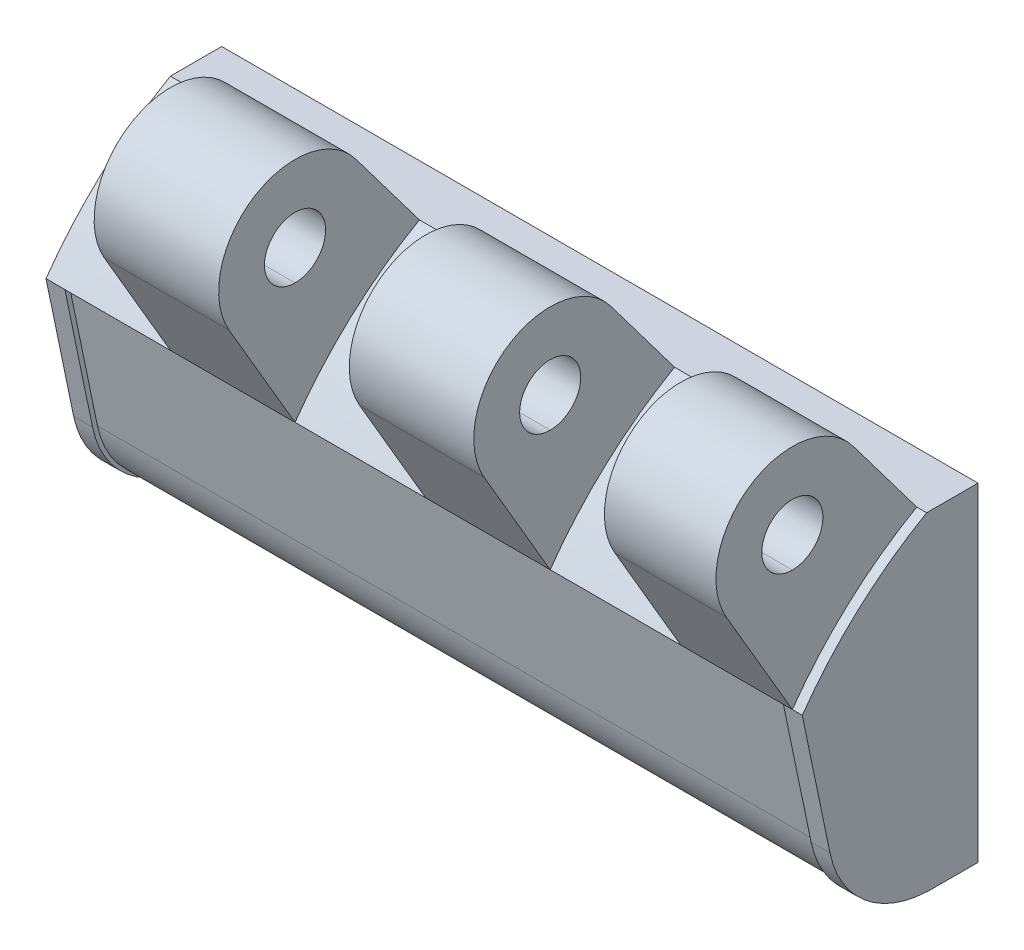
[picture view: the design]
ISO-10303-21;
HEADER;
FILE_DESCRIPTION(('STEP AP214'),'2;1');
FILE_NAME('part.step','',(''),(''),'','','');
FILE_SCHEMA(('AUTOMOTIVE_DESIGN { 1 0 10303 214 1 1 1 1 }'));
ENDSEC;
DATA;
#1=APPLICATION_CONTEXT('core data for automotive mechanical design processes');
#2=APPLICATION_PROTOCOL_DEFINITION('international standard','automotive_design',2000,#1);
#3=PRODUCT_CONTEXT('',#1,'mechanical');
#4=PRODUCT('Part','Part','',(#3));
#5=PRODUCT_RELATED_PRODUCT_CATEGORY('part','',(#4));
#6=PRODUCT_DEFINITION_FORMATION('','',#4);
#7=PRODUCT_DEFINITION_CONTEXT('part definition',#1,'design');
#8=PRODUCT_DEFINITION('design','',#6,#7);
#9=PRODUCT_DEFINITION_SHAPE('','',#8);
#10=(LENGTH_UNIT() NAMED_UNIT(*) SI_UNIT(.MILLI.,.METRE.));
#11=(NAMED_UNIT(*) PLANE_ANGLE_UNIT() SI_UNIT($,.RADIAN.));
#12=(NAMED_UNIT(*) SI_UNIT($,.STERADIAN.) SOLID_ANGLE_UNIT());
#13=UNCERTAINTY_MEASURE_WITH_UNIT(LENGTH_MEASURE(1.E-05),#10,'distance_accuracy_value','');
#14=(GEOMETRIC_REPRESENTATION_CONTEXT(3) GLOBAL_UNCERTAINTY_ASSIGNED_CONTEXT((#13)) GLOBAL_UNIT_ASSIGNED_CONTEXT((#10,
#11,#12)) REPRESENTATION_CONTEXT('',''));
#15=CARTESIAN_POINT('',(0.,0.,0.));
#16=DIRECTION('',(0.,0.,1.));
#17=DIRECTION('',(1.,0.,0.));
#18=AXIS2_PLACEMENT_3D('',#15,#16,#17);
#19=CARTESIAN_POINT('',(38.63875,-2.8772598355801,8.51410225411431));
#20=DIRECTION('',(0.,0.203476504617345,-0.979079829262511));
#21=DIRECTION('',(0.,-0.979079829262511,-0.203476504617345));
#22=AXIS2_PLACEMENT_3D('',#19,#20,#21);
#23=PLANE('',#22);
#24=CARTESIAN_POINT('',(0.,0.,9.11206654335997));
#25=DIRECTION('',(0.,0.203476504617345,-0.979079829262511));
#26=DIRECTION('',(0.,-0.979079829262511,-0.203476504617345));
#27=AXIS2_PLACEMENT_3D('',#24,#25,#26);
#28=ELLIPSE('',#27,5.36217767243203,5.25);
#29=CARTESIAN_POINT('',(0.,5.25,10.2031437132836));
#30=VERTEX_POINT('',#29);
#31=CARTESIAN_POINT('',(4.3913410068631,-2.8772598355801,8.51410225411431));
#32=VERTEX_POINT('',#31);
#33=EDGE_CURVE('E1546',#30,#32,#28,.T.);
#34=ORIENTED_EDGE('',*,*,#33,.T.);
#35=DIRECTION('',(1.,0.,0.));
#36=VECTOR('',#35,1.);
#37=CARTESIAN_POINT('',(38.63875,-2.8772598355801,8.51410225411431));
#38=LINE('',#37,#36);
#39=CARTESIAN_POINT('',(-4.3913410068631,-2.8772598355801,8.51410225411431));
#40=VERTEX_POINT('',#39);
#41=EDGE_CURVE('E398',#32,#40,#38,.F.);
#42=ORIENTED_EDGE('',*,*,#41,.T.);
#43=CARTESIAN_POINT('',(0.,0.,9.11206654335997));
#44=DIRECTION('',(0.,0.203476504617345,-0.979079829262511));
#45=DIRECTION('',(0.,-0.979079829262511,-0.203476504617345));
#46=AXIS2_PLACEMENT_3D('',#43,#44,#45);
#47=ELLIPSE('',#46,5.36217767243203,5.25);
#48=EDGE_CURVE('E607',#40,#30,#47,.T.);
#49=ORIENTED_EDGE('',*,*,#48,.T.);
#50=EDGE_LOOP('',(#34,#42,#49));
#51=FACE_BOUND('',#50,.T.);
#52=ADVANCED_FACE('F14',(#51),#23,.T.);
#53=CARTESIAN_POINT('',(38.63875,-1.75,3.09));
#54=DIRECTION('',(1.,0.,0.));
#55=DIRECTION('',(0.,1.,0.));
#56=AXIS2_PLACEMENT_3D('',#53,#54,#55);
#57=CYLINDRICAL_SURFACE('',#56,5.54);
#58=CARTESIAN_POINT('',(0.,-5.25,7.3843684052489));
#59=CARTESIAN_POINT('',(-0.133828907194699,-5.25003375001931,7.38428145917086));
#60=CARTESIAN_POINT('',(-0.267610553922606,-5.2448846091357,7.38853693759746));
#61=CARTESIAN_POINT('',(-0.533720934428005,-5.22449303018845,7.40506712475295));
#62=CARTESIAN_POINT('',(-0.666051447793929,-5.20926480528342,7.41733054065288));
#63=CARTESIAN_POINT('',(-0.926970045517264,-5.16918804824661,7.44905462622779));
#64=CARTESIAN_POINT('',(-1.05558234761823,-5.1444374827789,7.46844191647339));
#65=CARTESIAN_POINT('',(-1.30960855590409,-5.08570777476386,7.51335022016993));
#66=CARTESIAN_POINT('',(-1.43502144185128,-5.0517257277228,7.53887316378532));
#67=CARTESIAN_POINT('',(-1.68130762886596,-4.97516280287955,7.59468067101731));
#68=CARTESIAN_POINT('',(-1.80220198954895,-4.9326299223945,7.62493845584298));
#69=CARTESIAN_POINT('',(-2.03969557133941,-4.83925951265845,7.68905316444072));
#70=CARTESIAN_POINT('',(-2.15629501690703,-4.78842241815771,7.72290989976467));
#71=CARTESIAN_POINT('',(-2.50013407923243,-4.62348229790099,7.82832401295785));
#72=CARTESIAN_POINT('',(-2.72060185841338,-4.49720570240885,7.90352608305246));
#73=CARTESIAN_POINT('',(-3.05164226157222,-4.27449143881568,8.02225033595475));
#74=CARTESIAN_POINT('',(-3.16919768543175,-4.188081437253,8.0656944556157));
#75=CARTESIAN_POINT('',(-3.39710991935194,-4.00542845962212,8.15110607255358));
#76=CARTESIAN_POINT('',(-3.50746471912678,-3.90918275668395,8.19307315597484));
#77=CARTESIAN_POINT('',(-3.71996372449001,-3.70752770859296,8.27376771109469));
#78=CARTESIAN_POINT('',(-3.82213447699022,-3.6021505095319,8.31250567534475));
#79=CARTESIAN_POINT('',(-4.01794535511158,-3.38234290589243,8.38532231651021));
#80=CARTESIAN_POINT('',(-4.11159227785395,-3.26791985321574,8.41940471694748));
#81=CARTESIAN_POINT('',(-4.23368735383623,-3.10506736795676,8.46191586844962));
#82=CARTESIAN_POINT('',(-4.26616032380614,-3.06030152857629,8.47301775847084));
#83=CARTESIAN_POINT('',(-4.32976362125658,-2.96963143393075,8.4942821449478));
#84=CARTESIAN_POINT('',(-4.36089439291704,-2.92372756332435,8.50444495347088));
#85=CARTESIAN_POINT('',(-4.39134100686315,-2.87725983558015,8.5141022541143));
#86=B_SPLINE_CURVE_WITH_KNOTS('',3,(#58,#59,#60,#61,#62,#63,#64,#65,#66,#67,#68,#69,#70,#71,#72,
#73,#74,#75,#76,#77,#78,#79,#80,#81,#82,#83,#84,#85),.UNSPECIFIED.,.F.,.F.,(4,2,2,2,2,2,2,2,2,2,
2,2,2,4),(0.,0.401244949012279,0.80192527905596,1.19858908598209,1.59537783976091,
1.98999859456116,2.38459869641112,3.1763987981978,3.63270260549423,4.08913326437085,
4.54401777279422,4.99853630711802,5.16772855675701,5.33686437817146),.UNSPECIFIED.);
#87=CARTESIAN_POINT('',(0.,-5.25,7.3843684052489));
#88=VERTEX_POINT('',#87);
#89=EDGE_CURVE('E600',#88,#40,#86,.T.);
#90=ORIENTED_EDGE('',*,*,#89,.T.);
#91=ORIENTED_EDGE('',*,*,#41,.F.);
#92=CARTESIAN_POINT('',(4.3913410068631,-2.8772598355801,8.51410225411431));
#93=CARTESIAN_POINT('',(4.30901059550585,-3.00292273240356,8.48799614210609));
#94=CARTESIAN_POINT('',(4.22168764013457,-3.12442415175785,8.45818131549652));
#95=CARTESIAN_POINT('',(4.03796771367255,-3.35848364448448,8.39274465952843));
#96=CARTESIAN_POINT('',(3.94158066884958,-3.47105125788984,8.3571291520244));
#97=CARTESIAN_POINT('',(3.7401855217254,-3.68719352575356,8.28153449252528));
#98=CARTESIAN_POINT('',(3.63515445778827,-3.79074261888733,8.24154361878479));
#99=CARTESIAN_POINT('',(3.41738224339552,-3.98818571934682,8.15888554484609));
#100=CARTESIAN_POINT('',(3.30463881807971,-4.08207685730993,8.11621755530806));
#101=CARTESIAN_POINT('',(2.95635398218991,-4.34828784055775,7.98685733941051));
#102=CARTESIAN_POINT('',(2.70992059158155,-4.5060387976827,7.89847178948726));
#103=CARTESIAN_POINT('',(2.32219866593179,-4.71075307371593,7.77315807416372));
#104=CARTESIAN_POINT('',(2.19014120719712,-4.7736074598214,7.73264865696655));
#105=CARTESIAN_POINT('',(1.92014141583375,-4.8884615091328,7.65578801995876));
#106=CARTESIAN_POINT('',(1.78219922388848,-4.94046143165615,7.61943670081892));
#107=CARTESIAN_POINT('',(1.51214189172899,-5.02936562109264,7.55543720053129));
#108=CARTESIAN_POINT('',(1.38042076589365,-5.06713507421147,7.52732956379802));
#109=CARTESIAN_POINT('',(1.11328601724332,-5.13244464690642,7.47775012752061));
#110=CARTESIAN_POINT('',(0.977874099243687,-5.15998940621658,7.45627531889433));
#111=CARTESIAN_POINT('',(0.702935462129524,-5.20460806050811,7.42106346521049));
#112=CARTESIAN_POINT('',(0.563381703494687,-5.22157877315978,7.40740277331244));
#113=CARTESIAN_POINT('',(0.352852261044,-5.23860422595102,7.39363653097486));
#114=CARTESIAN_POINT('',(0.282404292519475,-5.242874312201,7.3901684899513));
#115=CARTESIAN_POINT('',(0.141308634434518,-5.24857303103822,7.38553183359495));
#116=CARTESIAN_POINT('',(0.0706609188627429,-5.25000127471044,7.38436353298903));
#117=CARTESIAN_POINT('',(0.,-5.25,7.38436840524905));
#118=B_SPLINE_CURVE_WITH_KNOTS('',3,(#92,#93,#94,#95,#96,#97,#98,#99,#100,#101,#102,#103,#104,
#105,#106,#107,#108,#109,#110,#111,#112,#113,#114,#115,#116,#117),.UNSPECIFIED.,.F.,.F.,(4,2,2,
2,2,2,2,2,2,2,2,2,4),(0.,0.457120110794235,0.913745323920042,1.37162527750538,1.82964087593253,
2.74190293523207,3.1967769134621,3.65164002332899,4.07075607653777,4.48968171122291,
4.91263373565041,5.12453779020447,5.33647084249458),.UNSPECIFIED.);
#119=EDGE_CURVE('E576',#32,#88,#118,.T.);
#120=ORIENTED_EDGE('',*,*,#119,.T.);
#121=EDGE_LOOP('',(#90,#91,#120));
#122=FACE_BOUND('',#121,.T.);
#123=ADVANCED_FACE('F609',(#122),#57,.F.);
#124=CARTESIAN_POINT('',(38.63875,-2.8772598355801,8.51410225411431));
#125=DIRECTION('',(0.,0.203476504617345,-0.979079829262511));
#126=DIRECTION('',(0.,-0.979079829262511,-0.203476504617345));
#127=AXIS2_PLACEMENT_3D('',#124,#125,#126);
#128=PLANE('',#127);
#129=CARTESIAN_POINT('',(30.5,0.,9.11206654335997));
#130=DIRECTION('',(0.,0.203476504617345,-0.979079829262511));
#131=DIRECTION('',(0.,-0.979079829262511,-0.203476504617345));
#132=AXIS2_PLACEMENT_3D('',#129,#130,#131);
#133=ELLIPSE('',#132,5.36217767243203,5.25);
#134=CARTESIAN_POINT('',(30.5,5.25,10.2031437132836));
#135=VERTEX_POINT('',#134);
#136=CARTESIAN_POINT('',(34.8913410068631,-2.8772598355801,8.51410225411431));
#137=VERTEX_POINT('',#136);
#138=EDGE_CURVE('E551',#135,#137,#133,.T.);
#139=ORIENTED_EDGE('',*,*,#138,.T.);
#140=DIRECTION('',(1.,0.,0.));
#141=VECTOR('',#140,1.);
#142=CARTESIAN_POINT('',(38.63875,-2.8772598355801,8.51410225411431));
#143=LINE('',#142,#141);
#144=CARTESIAN_POINT('',(26.1086589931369,-2.8772598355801,8.51410225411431));
#145=VERTEX_POINT('',#144);
#146=EDGE_CURVE('E396',#137,#145,#143,.F.);
#147=ORIENTED_EDGE('',*,*,#146,.T.);
#148=CARTESIAN_POINT('',(30.5,0.,9.11206654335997));
#149=DIRECTION('',(0.,0.203476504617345,-0.979079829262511));
#150=DIRECTION('',(0.,-0.979079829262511,-0.203476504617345));
#151=AXIS2_PLACEMENT_3D('',#148,#149,#150);
#152=ELLIPSE('',#151,5.36217767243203,5.25);
#153=EDGE_CURVE('E574',#145,#135,#152,.T.);
#154=ORIENTED_EDGE('',*,*,#153,.T.);
#155=EDGE_LOOP('',(#139,#147,#154));
#156=FACE_BOUND('',#155,.T.);
#157=ADVANCED_FACE('F562',(#156),#128,.T.);
#158=CARTESIAN_POINT('',(38.63875,-1.75,3.09));
#159=DIRECTION('',(1.,0.,0.));
#160=DIRECTION('',(0.,1.,0.));
#161=AXIS2_PLACEMENT_3D('',#158,#159,#160);
#162=CYLINDRICAL_SURFACE('',#161,5.54);
#163=CARTESIAN_POINT('',(30.5,-5.25,7.3843684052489));
#164=CARTESIAN_POINT('',(30.3661710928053,-5.25003375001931,7.38428145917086));
#165=CARTESIAN_POINT('',(30.2323894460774,-5.2448846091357,7.38853693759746));
#166=CARTESIAN_POINT('',(29.966279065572,-5.22449303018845,7.40506712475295));
#167=CARTESIAN_POINT('',(29.8339485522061,-5.20926480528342,7.41733054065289));
#168=CARTESIAN_POINT('',(29.5730299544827,-5.16918804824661,7.44905462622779));
#169=CARTESIAN_POINT('',(29.4444176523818,-5.1444374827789,7.46844191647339));
#170=CARTESIAN_POINT('',(29.1903914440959,-5.08570777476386,7.51335022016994));
#171=CARTESIAN_POINT('',(29.0649785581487,-5.0517257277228,7.53887316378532));
#172=CARTESIAN_POINT('',(28.818692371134,-4.97516280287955,7.59468067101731));
#173=CARTESIAN_POINT('',(28.697798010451,-4.93262992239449,7.62493845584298));
#174=CARTESIAN_POINT('',(28.4603044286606,-4.83925951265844,7.68905316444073));
#175=CARTESIAN_POINT('',(28.343704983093,-4.7884224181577,7.72290989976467));
#176=CARTESIAN_POINT('',(27.9998659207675,-4.62348229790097,7.82832401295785));
#177=CARTESIAN_POINT('',(27.7793981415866,-4.49720570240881,7.90352608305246));
#178=CARTESIAN_POINT('',(27.4483577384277,-4.27449143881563,8.02225033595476));
#179=CARTESIAN_POINT('',(27.3308023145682,-4.18808143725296,8.06569445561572));
#180=CARTESIAN_POINT('',(27.102890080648,-4.00542845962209,8.1511060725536));
#181=CARTESIAN_POINT('',(26.9925352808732,-3.90918275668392,8.19307315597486));
#182=CARTESIAN_POINT('',(26.78003627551,-3.70752770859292,8.27376771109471));
#183=CARTESIAN_POINT('',(26.6778655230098,-3.60215050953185,8.31250567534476));
#184=CARTESIAN_POINT('',(26.4820546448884,-3.38234290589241,8.38532231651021));
#185=CARTESIAN_POINT('',(26.388407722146,-3.26791985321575,8.41940471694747));
#186=CARTESIAN_POINT('',(26.2663126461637,-3.10506736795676,8.46191586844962));
#187=CARTESIAN_POINT('',(26.2338396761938,-3.06030152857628,8.47301775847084));
#188=CARTESIAN_POINT('',(26.1702363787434,-2.96963143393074,8.4942821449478));
#189=CARTESIAN_POINT('',(26.139105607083,-2.92372756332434,8.50444495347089));
#190=CARTESIAN_POINT('',(26.1086589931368,-2.87725983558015,8.5141022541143));
#191=B_SPLINE_CURVE_WITH_KNOTS('',3,(#163,#164,#165,#166,#167,#168,#169,#170,#171,#172,#173,
#174,#175,#176,#177,#178,#179,#180,#181,#182,#183,#184,#185,#186,#187,#188,#189,#190),
.UNSPECIFIED.,.F.,.F.,(4,2,2,2,2,2,2,2,2,2,2,2,2,4),(0.,0.401244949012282,0.801925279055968,
1.1985890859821,1.59537783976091,1.98999859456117,2.38459869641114,3.17639879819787,
3.63270260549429,4.0891332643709,4.54401777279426,4.99853630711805,5.16772855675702,
5.33686437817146),.UNSPECIFIED.);
#192=CARTESIAN_POINT('',(30.5,-5.25,7.3843684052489));
#193=VERTEX_POINT('',#192);
#194=EDGE_CURVE('E567',#193,#145,#191,.T.);
#195=ORIENTED_EDGE('',*,*,#194,.T.);
#196=ORIENTED_EDGE('',*,*,#146,.F.);
#197=CARTESIAN_POINT('',(34.8913410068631,-2.8772598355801,8.51410225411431));
#198=CARTESIAN_POINT('',(34.8090105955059,-3.00292273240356,8.48799614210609));
#199=CARTESIAN_POINT('',(34.7216876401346,-3.12442415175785,8.45818131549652));
#200=CARTESIAN_POINT('',(34.5379677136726,-3.35848364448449,8.39274465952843));
#201=CARTESIAN_POINT('',(34.4415806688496,-3.47105125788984,8.3571291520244));
#202=CARTESIAN_POINT('',(34.2401855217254,-3.68719352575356,8.28153449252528));
#203=CARTESIAN_POINT('',(34.1351544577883,-3.79074261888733,8.24154361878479));
#204=CARTESIAN_POINT('',(33.9173822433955,-3.98818571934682,8.15888554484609));
#205=CARTESIAN_POINT('',(33.8046388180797,-4.08207685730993,8.11621755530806));
#206=CARTESIAN_POINT('',(33.4563539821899,-4.34828784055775,7.98685733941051));
#207=CARTESIAN_POINT('',(33.2099205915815,-4.5060387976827,7.89847178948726));
#208=CARTESIAN_POINT('',(32.8221986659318,-4.71075307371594,7.77315807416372));
#209=CARTESIAN_POINT('',(32.6901412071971,-4.7736074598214,7.73264865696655));
#210=CARTESIAN_POINT('',(32.4201414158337,-4.8884615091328,7.65578801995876));
#211=CARTESIAN_POINT('',(32.2821992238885,-4.94046143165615,7.61943670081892));
#212=CARTESIAN_POINT('',(32.012141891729,-5.02936562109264,7.55543720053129));
#213=CARTESIAN_POINT('',(31.8804207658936,-5.06713507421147,7.52732956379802));
#214=CARTESIAN_POINT('',(31.6132860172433,-5.13244464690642,7.47775012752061));
#215=CARTESIAN_POINT('',(31.4778740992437,-5.15998940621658,7.45627531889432));
#216=CARTESIAN_POINT('',(31.2029354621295,-5.20460806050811,7.42106346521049));
#217=CARTESIAN_POINT('',(31.0633817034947,-5.22157877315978,7.40740277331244));
#218=CARTESIAN_POINT('',(30.852852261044,-5.23860422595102,7.39363653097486));
#219=CARTESIAN_POINT('',(30.7824042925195,-5.242874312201,7.3901684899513));
#220=CARTESIAN_POINT('',(30.6413086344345,-5.24857303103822,7.38553183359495));
#221=CARTESIAN_POINT('',(30.5706609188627,-5.25000127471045,7.38436353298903));
#222=CARTESIAN_POINT('',(30.5,-5.25,7.38436840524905));
#223=B_SPLINE_CURVE_WITH_KNOTS('',3,(#197,#198,#199,#200,#201,#202,#203,#204,#205,#206,#207,
#208,#209,#210,#211,#212,#213,#214,#215,#216,#217,#218,#219,#220,#221,#222),.UNSPECIFIED.,.F.,
.F.,(4,2,2,2,2,2,2,2,2,2,2,2,4),(0.,0.457120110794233,0.913745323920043,1.37162527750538,
1.82964087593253,2.74190293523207,3.1967769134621,3.65164002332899,4.07075607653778,
4.48968171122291,4.91263373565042,5.12453779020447,5.33647084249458),.UNSPECIFIED.);
#224=EDGE_CURVE('E542',#137,#193,#223,.T.);
#225=ORIENTED_EDGE('',*,*,#224,.T.);
#226=EDGE_LOOP('',(#195,#196,#225));
#227=FACE_BOUND('',#226,.T.);
#228=ADVANCED_FACE('F557',(#227),#162,.F.);
#229=CARTESIAN_POINT('',(38.7625,-1.75,3.09));
#230=DIRECTION('',(1.,0.,0.));
#231=DIRECTION('',(0.,1.,0.));
#232=AXIS2_PLACEMENT_3D('',#229,#230,#231);
#233=CYLINDRICAL_SURFACE('',#232,5.54);
#234=CARTESIAN_POINT('',(-8.2625,-1.75,3.09));
#235=DIRECTION('',(1.,0.,0.));
#236=DIRECTION('',(0.,1.,0.));
#237=AXIS2_PLACEMENT_3D('',#234,#235,#236);
#238=CIRCLE('',#237,5.54);
#239=CARTESIAN_POINT('',(-8.2625,-7.2834549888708,3.35921345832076));
#240=VERTEX_POINT('',#239);
#241=CARTESIAN_POINT('',(-8.2625,-2.8772598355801,8.51410225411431));
#242=VERTEX_POINT('',#241);
#243=EDGE_CURVE('E539',#240,#242,#238,.F.);
#244=ORIENTED_EDGE('',*,*,#243,.F.);
#245=DIRECTION('',(1.,0.,0.));
#246=VECTOR('',#245,1.);
#247=CARTESIAN_POINT('',(38.7625,-7.2834549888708,3.35921345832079));
#248=LINE('',#247,#246);
#249=CARTESIAN_POINT('',(-8.13875,-7.2834549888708,3.35921345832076));
#250=VERTEX_POINT('',#249);
#251=EDGE_CURVE('E327',#240,#250,#248,.T.);
#252=ORIENTED_EDGE('',*,*,#251,.T.);
#253=CARTESIAN_POINT('',(-8.13875,-1.75,3.09));
#254=DIRECTION('',(1.,0.,0.));
#255=DIRECTION('',(0.,1.,0.));
#256=AXIS2_PLACEMENT_3D('',#253,#254,#255);
#257=CIRCLE('',#256,5.54);
#258=CARTESIAN_POINT('',(-8.13875,-2.8772598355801,8.51410225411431));
#259=VERTEX_POINT('',#258);
#260=EDGE_CURVE('E17',#250,#259,#257,.F.);
#261=ORIENTED_EDGE('',*,*,#260,.T.);
#262=DIRECTION('',(-1.,0.,0.));
#263=VECTOR('',#262,1.);
#264=CARTESIAN_POINT('',(38.7625,-2.8772598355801,8.51410225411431));
#265=LINE('',#264,#263);
#266=EDGE_CURVE('E315',#259,#242,#265,.T.);
#267=ORIENTED_EDGE('',*,*,#266,.T.);
#268=EDGE_LOOP('',(#244,#252,#261,#267));
#269=FACE_BOUND('',#268,.T.);
#270=ADVANCED_FACE('F330',(#269),#233,.T.);
#271=CARTESIAN_POINT('',(38.7625,-2.8772598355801,8.51410225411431));
#272=DIRECTION('',(0.,0.203476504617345,-0.979079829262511));
#273=DIRECTION('',(0.,-0.979079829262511,-0.203476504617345));
#274=AXIS2_PLACEMENT_3D('',#271,#272,#273);
#275=PLANE('',#274);
#276=DIRECTION('',(-1.,0.,0.));
#277=VECTOR('',#276,1.);
#278=CARTESIAN_POINT('',(38.7625,5.5926726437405,10.2743593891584));
#279=LINE('',#278,#277);
#280=CARTESIAN_POINT('',(-8.2625,5.5926726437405,10.2743593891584));
#281=VERTEX_POINT('',#280);
#282=CARTESIAN_POINT('',(-8.13875,5.5926726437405,10.2743593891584));
#283=VERTEX_POINT('',#282);
#284=EDGE_CURVE('E326',#281,#283,#279,.F.);
#285=ORIENTED_EDGE('',*,*,#284,.F.);
#286=DIRECTION('',(0.,0.979079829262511,0.203476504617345));
#287=VECTOR('',#286,1.);
#288=CARTESIAN_POINT('',(-8.2625,-2.8772598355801,8.51410225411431));
#289=LINE('',#288,#287);
#290=EDGE_CURVE('E322',#242,#281,#289,.T.);
#291=ORIENTED_EDGE('',*,*,#290,.F.);
#292=ORIENTED_EDGE('',*,*,#266,.F.);
#293=DIRECTION('',(0.,0.979079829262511,0.203476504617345));
#294=VECTOR('',#293,1.);
#295=CARTESIAN_POINT('',(-8.13875,-2.8772598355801,8.51410225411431));
#296=LINE('',#295,#294);
#297=EDGE_CURVE('E319',#259,#283,#296,.T.);
#298=ORIENTED_EDGE('',*,*,#297,.T.);
#299=EDGE_LOOP('',(#285,#291,#292,#298));
#300=FACE_BOUND('',#299,.T.);
#301=ADVANCED_FACE('F317',(#300),#275,.F.);
#302=CARTESIAN_POINT('',(6.8,15.5,11.5));
#303=DIRECTION('',(1.,0.,0.));
#304=DIRECTION('',(0.,1.,0.));
#305=AXIS2_PLACEMENT_3D('',#302,#303,#304);
#306=CYLINDRICAL_SURFACE('',#305,2.);
#307=CARTESIAN_POINT('',(6.8,15.5,11.5));
#308=DIRECTION('',(1.,0.,0.));
#309=DIRECTION('',(0.,1.,0.));
#310=AXIS2_PLACEMENT_3D('',#307,#308,#309);
#311=CIRCLE('',#310,2.);
#312=CARTESIAN_POINT('',(6.8,13.5,11.5));
#313=VERTEX_POINT('',#312);
#314=CARTESIAN_POINT('',(6.8,17.5,11.5));
#315=VERTEX_POINT('',#314);
#316=EDGE_CURVE('E525',#313,#315,#311,.F.);
#317=ORIENTED_EDGE('',*,*,#316,.F.);
#318=DIRECTION('',(1.,0.,0.));
#319=VECTOR('',#318,1.);
#320=CARTESIAN_POINT('',(6.8,13.5,11.5));
#321=LINE('',#320,#319);
#322=CARTESIAN_POINT('',(-1.35,13.5,11.5));
#323=VERTEX_POINT('',#322);
#324=EDGE_CURVE('E386',#313,#323,#321,.F.);
#325=ORIENTED_EDGE('',*,*,#324,.T.);
#326=CARTESIAN_POINT('',(-1.35,15.5,11.5));
#327=DIRECTION('',(1.,0.,0.));
#328=DIRECTION('',(0.,1.,0.));
#329=AXIS2_PLACEMENT_3D('',#326,#327,#328);
#330=CIRCLE('',#329,2.);
#331=CARTESIAN_POINT('',(-1.35,17.5,11.5));
#332=VERTEX_POINT('',#331);
#333=EDGE_CURVE('E537',#323,#332,#330,.F.);
#334=ORIENTED_EDGE('',*,*,#333,.T.);
#335=DIRECTION('',(1.,0.,0.));
#336=VECTOR('',#335,1.);
#337=CARTESIAN_POINT('',(6.8,17.5,11.5));
#338=LINE('',#337,#336);
#339=EDGE_CURVE('E384',#332,#315,#338,.T.);
#340=ORIENTED_EDGE('',*,*,#339,.T.);
#341=EDGE_LOOP('',(#317,#325,#334,#340));
#342=FACE_BOUND('',#341,.T.);
#343=ADVANCED_FACE('F1104',(#342),#306,.F.);
#344=CARTESIAN_POINT('',(6.8,15.5,11.5));
#345=DIRECTION('',(1.,0.,0.));
#346=DIRECTION('',(0.,1.,0.));
#347=AXIS2_PLACEMENT_3D('',#344,#345,#346);
#348=CYLINDRICAL_SURFACE('',#347,2.);
#349=CARTESIAN_POINT('',(-1.35,15.5,11.5));
#350=DIRECTION('',(1.,0.,0.));
#351=DIRECTION('',(0.,1.,0.));
#352=AXIS2_PLACEMENT_3D('',#349,#350,#351);
#353=CIRCLE('',#352,2.);
#354=EDGE_CURVE('E534',#332,#323,#353,.F.);
#355=ORIENTED_EDGE('',*,*,#354,.T.);
#356=ORIENTED_EDGE('',*,*,#324,.F.);
#357=CARTESIAN_POINT('',(6.8,15.5,11.5));
#358=DIRECTION('',(1.,0.,0.));
#359=DIRECTION('',(0.,1.,0.));
#360=AXIS2_PLACEMENT_3D('',#357,#358,#359);
#361=CIRCLE('',#360,2.);
#362=EDGE_CURVE('E522',#315,#313,#361,.F.);
#363=ORIENTED_EDGE('',*,*,#362,.F.);
#364=ORIENTED_EDGE('',*,*,#339,.F.);
#365=EDGE_LOOP('',(#355,#356,#363,#364));
#366=FACE_BOUND('',#365,.T.);
#367=ADVANCED_FACE('F1108',(#366),#348,.F.);
#368=CARTESIAN_POINT('',(15.35,15.5,11.5));
#369=DIRECTION('',(-1.,0.,0.));
#370=DIRECTION('',(0.,-1.,0.));
#371=AXIS2_PLACEMENT_3D('',#368,#369,#370);
#372=CYLINDRICAL_SURFACE('',#371,2.);
#373=CARTESIAN_POINT('',(23.5,15.5,11.5));
#374=DIRECTION('',(-1.,0.,0.));
#375=DIRECTION('',(0.,-1.,0.));
#376=AXIS2_PLACEMENT_3D('',#373,#374,#375);
#377=CIRCLE('',#376,2.);
#378=CARTESIAN_POINT('',(23.5,13.5,11.5));
#379=VERTEX_POINT('',#378);
#380=CARTESIAN_POINT('',(23.5,17.5,11.5));
#381=VERTEX_POINT('',#380);
#382=EDGE_CURVE('E379',#379,#381,#377,.T.);
#383=ORIENTED_EDGE('',*,*,#382,.F.);
#384=DIRECTION('',(-1.,0.,0.));
#385=VECTOR('',#384,1.);
#386=CARTESIAN_POINT('',(15.35,13.5,11.5));
#387=LINE('',#386,#385);
#388=CARTESIAN_POINT('',(15.35,13.5,11.5));
#389=VERTEX_POINT('',#388);
#390=EDGE_CURVE('E382',#379,#389,#387,.T.);
#391=ORIENTED_EDGE('',*,*,#390,.T.);
#392=CARTESIAN_POINT('',(15.35,15.5,11.5));
#393=DIRECTION('',(-1.,0.,0.));
#394=DIRECTION('',(0.,-1.,0.));
#395=AXIS2_PLACEMENT_3D('',#392,#393,#394);
#396=CIRCLE('',#395,2.);
#397=CARTESIAN_POINT('',(15.35,17.5,11.5));
#398=VERTEX_POINT('',#397);
#399=EDGE_CURVE('E515',#389,#398,#396,.T.);
#400=ORIENTED_EDGE('',*,*,#399,.T.);
#401=DIRECTION('',(-1.,0.,0.));
#402=VECTOR('',#401,1.);
#403=CARTESIAN_POINT('',(15.35,17.5,11.5));
#404=LINE('',#403,#402);
#405=EDGE_CURVE('E372',#398,#381,#404,.F.);
#406=ORIENTED_EDGE('',*,*,#405,.T.);
#407=EDGE_LOOP('',(#383,#391,#400,#406));
#408=FACE_BOUND('',#407,.T.);
#409=ADVANCED_FACE('F1110',(#408),#372,.F.);
#410=CARTESIAN_POINT('',(15.35,15.5,11.5));
#411=DIRECTION('',(-1.,0.,0.));
#412=DIRECTION('',(0.,-1.,0.));
#413=AXIS2_PLACEMENT_3D('',#410,#411,#412);
#414=CYLINDRICAL_SURFACE('',#413,2.);
#415=CARTESIAN_POINT('',(15.35,15.5,11.5));
#416=DIRECTION('',(-1.,0.,0.));
#417=DIRECTION('',(0.,-1.,0.));
#418=AXIS2_PLACEMENT_3D('',#415,#416,#417);
#419=CIRCLE('',#418,2.);
#420=EDGE_CURVE('E518',#398,#389,#419,.T.);
#421=ORIENTED_EDGE('',*,*,#420,.T.);
#422=ORIENTED_EDGE('',*,*,#390,.F.);
#423=CARTESIAN_POINT('',(23.5,15.5,11.5));
#424=DIRECTION('',(-1.,0.,0.));
#425=DIRECTION('',(0.,-1.,0.));
#426=AXIS2_PLACEMENT_3D('',#423,#424,#425);
#427=CIRCLE('',#426,2.);
#428=EDGE_CURVE('E508',#381,#379,#427,.T.);
#429=ORIENTED_EDGE('',*,*,#428,.F.);
#430=ORIENTED_EDGE('',*,*,#405,.F.);
#431=EDGE_LOOP('',(#421,#422,#429,#430));
#432=FACE_BOUND('',#431,.T.);
#433=ADVANCED_FACE('F1117',(#432),#414,.F.);
#434=CARTESIAN_POINT('',(6.8,12.9766151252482,15.8165412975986));
#435=DIRECTION('',(0.,-0.504676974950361,0.863308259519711));
#436=DIRECTION('',(0.,0.863308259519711,0.504676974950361));
#437=AXIS2_PLACEMENT_3D('',#434,#435,#436);
#438=PLANE('',#437);
#439=DIRECTION('',(0.,-0.863308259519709,-0.504676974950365));
#440=VECTOR('',#439,1.);
#441=CARTESIAN_POINT('',(6.8,12.9766151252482,15.8165412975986));
#442=LINE('',#441,#440);
#443=CARTESIAN_POINT('',(6.8,12.9766151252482,15.8165412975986));
#444=VERTEX_POINT('',#443);
#445=CARTESIAN_POINT('',(6.8,5.59267264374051,11.5));
#446=VERTEX_POINT('',#445);
#447=EDGE_CURVE('E528',#444,#446,#442,.T.);
#448=ORIENTED_EDGE('',*,*,#447,.F.);
#449=DIRECTION('',(1.,0.,0.));
#450=VECTOR('',#449,1.);
#451=CARTESIAN_POINT('',(6.8,12.9766151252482,15.8165412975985));
#452=LINE('',#451,#450);
#453=CARTESIAN_POINT('',(-1.35,12.9766151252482,15.8165412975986));
#454=VERTEX_POINT('',#453);
#455=EDGE_CURVE('E388',#454,#444,#452,.T.);
#456=ORIENTED_EDGE('',*,*,#455,.F.);
#457=DIRECTION('',(0.,-0.863308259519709,-0.504676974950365));
#458=VECTOR('',#457,1.);
#459=CARTESIAN_POINT('',(-1.35,12.9766151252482,15.8165412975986));
#460=LINE('',#459,#458);
#461=CARTESIAN_POINT('',(-1.35,5.59267264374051,11.5));
#462=VERTEX_POINT('',#461);
#463=EDGE_CURVE('E533',#454,#462,#460,.T.);
#464=ORIENTED_EDGE('',*,*,#463,.T.);
#465=DIRECTION('',(-1.,0.,0.));
#466=VECTOR('',#465,1.);
#467=CARTESIAN_POINT('',(38.7625,5.5926726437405,11.5));
#468=LINE('',#467,#466);
#469=EDGE_CURVE('E792',#462,#446,#468,.F.);
#470=ORIENTED_EDGE('',*,*,#469,.T.);
#471=EDGE_LOOP('',(#448,#456,#464,#470));
#472=FACE_BOUND('',#471,.T.);
#473=ADVANCED_FACE('F1092',(#472),#438,.T.);
#474=CARTESIAN_POINT('',(15.35,5.5926726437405,11.5));
#475=DIRECTION('',(0.,-0.504676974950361,0.863308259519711));
#476=DIRECTION('',(0.,0.863308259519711,0.504676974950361));
#477=AXIS2_PLACEMENT_3D('',#474,#475,#476);
#478=PLANE('',#477);
#479=DIRECTION('',(0.,-0.863308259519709,-0.504676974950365));
#480=VECTOR('',#479,1.);
#481=CARTESIAN_POINT('',(15.35,12.9766151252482,15.8165412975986));
#482=LINE('',#481,#480);
#483=CARTESIAN_POINT('',(15.35,12.9766151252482,15.8165412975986));
#484=VERTEX_POINT('',#483);
#485=CARTESIAN_POINT('',(15.35,5.59267264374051,11.5));
#486=VERTEX_POINT('',#485);
#487=EDGE_CURVE('E521',#484,#486,#482,.T.);
#488=ORIENTED_EDGE('',*,*,#487,.T.);
#489=DIRECTION('',(-1.,0.,0.));
#490=VECTOR('',#489,1.);
#491=CARTESIAN_POINT('',(38.7625,5.5926726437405,11.5));
#492=LINE('',#491,#490);
#493=CARTESIAN_POINT('',(23.5,5.59267264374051,11.5));
#494=VERTEX_POINT('',#493);
#495=EDGE_CURVE('E794',#486,#494,#492,.F.);
#496=ORIENTED_EDGE('',*,*,#495,.T.);
#497=DIRECTION('',(0.,-0.863308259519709,-0.504676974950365));
#498=VECTOR('',#497,1.);
#499=CARTESIAN_POINT('',(23.5,12.9766151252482,15.8165412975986));
#500=LINE('',#499,#498);
#501=CARTESIAN_POINT('',(23.5,12.9766151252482,15.8165412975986));
#502=VERTEX_POINT('',#501);
#503=EDGE_CURVE('E507',#502,#494,#500,.T.);
#504=ORIENTED_EDGE('',*,*,#503,.F.);
#505=DIRECTION('',(-1.,0.,0.));
#506=VECTOR('',#505,1.);
#507=CARTESIAN_POINT('',(15.35,12.9766151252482,15.8165412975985));
#508=LINE('',#507,#506);
#509=EDGE_CURVE('E377',#484,#502,#508,.F.);
#510=ORIENTED_EDGE('',*,*,#509,.F.);
#511=EDGE_LOOP('',(#488,#496,#504,#510));
#512=FACE_BOUND('',#511,.T.);
#513=ADVANCED_FACE('F1080',(#512),#478,.T.);
#514=CARTESIAN_POINT('',(32.05,15.5,11.5));
#515=DIRECTION('',(-1.,0.,0.));
#516=DIRECTION('',(0.,-1.,0.));
#517=AXIS2_PLACEMENT_3D('',#514,#515,#516);
#518=CYLINDRICAL_SURFACE('',#517,2.);
#519=CARTESIAN_POINT('',(39.35,15.5,11.5));
#520=DIRECTION('',(-1.,0.,0.));
#521=DIRECTION('',(0.,-1.,0.));
#522=AXIS2_PLACEMENT_3D('',#519,#520,#521);
#523=CIRCLE('',#522,2.);
#524=CARTESIAN_POINT('',(39.35,13.5,11.5));
#525=VERTEX_POINT('',#524);
#526=CARTESIAN_POINT('',(39.35,17.5,11.5));
#527=VERTEX_POINT('',#526);
#528=EDGE_CURVE('E367',#525,#527,#523,.T.);
#529=ORIENTED_EDGE('',*,*,#528,.F.);
#530=DIRECTION('',(-1.,0.,0.));
#531=VECTOR('',#530,1.);
#532=CARTESIAN_POINT('',(32.05,13.5,11.5));
#533=LINE('',#532,#531);
#534=CARTESIAN_POINT('',(32.05,13.5,11.5));
#535=VERTEX_POINT('',#534);
#536=EDGE_CURVE('E370',#525,#535,#533,.T.);
#537=ORIENTED_EDGE('',*,*,#536,.T.);
#538=CARTESIAN_POINT('',(32.05,15.5,11.5));
#539=DIRECTION('',(-1.,0.,0.));
#540=DIRECTION('',(0.,-1.,0.));
#541=AXIS2_PLACEMENT_3D('',#538,#539,#540);
#542=CIRCLE('',#541,2.);
#543=CARTESIAN_POINT('',(32.05,17.5,11.5));
#544=VERTEX_POINT('',#543);
#545=EDGE_CURVE('E498',#535,#544,#542,.T.);
#546=ORIENTED_EDGE('',*,*,#545,.T.);
#547=DIRECTION('',(-1.,0.,0.));
#548=VECTOR('',#547,1.);
#549=CARTESIAN_POINT('',(32.05,17.5,11.5));
#550=LINE('',#549,#548);
#551=EDGE_CURVE('E362',#544,#527,#550,.F.);
#552=ORIENTED_EDGE('',*,*,#551,.T.);
#553=EDGE_LOOP('',(#529,#537,#546,#552));
#554=FACE_BOUND('',#553,.T.);
#555=ADVANCED_FACE('F1428',(#554),#518,.F.);
#556=CARTESIAN_POINT('',(32.05,15.5,11.5));
#557=DIRECTION('',(-1.,0.,0.));
#558=DIRECTION('',(0.,-1.,0.));
#559=AXIS2_PLACEMENT_3D('',#556,#557,#558);
#560=CYLINDRICAL_SURFACE('',#559,2.);
#561=CARTESIAN_POINT('',(32.05,15.5,11.5));
#562=DIRECTION('',(-1.,0.,0.));
#563=DIRECTION('',(0.,-1.,0.));
#564=AXIS2_PLACEMENT_3D('',#561,#562,#563);
#565=CIRCLE('',#564,2.);
#566=EDGE_CURVE('E501',#544,#535,#565,.T.);
#567=ORIENTED_EDGE('',*,*,#566,.T.);
#568=ORIENTED_EDGE('',*,*,#536,.F.);
#569=CARTESIAN_POINT('',(39.35,15.5,11.5));
#570=DIRECTION('',(-1.,0.,0.));
#571=DIRECTION('',(0.,-1.,0.));
#572=AXIS2_PLACEMENT_3D('',#569,#570,#571);
#573=CIRCLE('',#572,2.);
#574=EDGE_CURVE('E491',#527,#525,#573,.T.);
#575=ORIENTED_EDGE('',*,*,#574,.F.);
#576=ORIENTED_EDGE('',*,*,#551,.F.);
#577=EDGE_LOOP('',(#567,#568,#575,#576));
#578=FACE_BOUND('',#577,.T.);
#579=ADVANCED_FACE('F1436',(#578),#560,.F.);
#580=CARTESIAN_POINT('',(32.05,5.5926726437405,11.5));
#581=DIRECTION('',(0.,-0.504676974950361,0.863308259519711));
#582=DIRECTION('',(0.,0.863308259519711,0.504676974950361));
#583=AXIS2_PLACEMENT_3D('',#580,#581,#582);
#584=PLANE('',#583);
#585=DIRECTION('',(-1.,0.,0.));
#586=VECTOR('',#585,1.);
#587=CARTESIAN_POINT('',(38.7625,5.5926726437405,11.5));
#588=LINE('',#587,#586);
#589=CARTESIAN_POINT('',(32.05,5.59267264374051,11.5));
#590=VERTEX_POINT('',#589);
#591=CARTESIAN_POINT('',(38.7625,5.5926726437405,11.5));
#592=VERTEX_POINT('',#591);
#593=EDGE_CURVE('E355',#590,#592,#588,.F.);
#594=ORIENTED_EDGE('',*,*,#593,.T.);
#595=DIRECTION('',(-1.,0.,0.));
#596=VECTOR('',#595,1.);
#597=CARTESIAN_POINT('',(32.05,5.5926726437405,11.5));
#598=LINE('',#597,#596);
#599=CARTESIAN_POINT('',(39.35,5.59267264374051,11.5));
#600=VERTEX_POINT('',#599);
#601=EDGE_CURVE('E360',#592,#600,#598,.F.);
#602=ORIENTED_EDGE('',*,*,#601,.T.);
#603=DIRECTION('',(0.,-0.863308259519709,-0.504676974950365));
#604=VECTOR('',#603,1.);
#605=CARTESIAN_POINT('',(39.35,12.9766151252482,15.8165412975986));
#606=LINE('',#605,#604);
#607=CARTESIAN_POINT('',(39.35,12.9766151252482,15.8165412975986));
#608=VERTEX_POINT('',#607);
#609=EDGE_CURVE('E490',#608,#600,#606,.T.);
#610=ORIENTED_EDGE('',*,*,#609,.F.);
#611=DIRECTION('',(-1.,0.,0.));
#612=VECTOR('',#611,1.);
#613=CARTESIAN_POINT('',(32.05,12.9766151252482,15.8165412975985));
#614=LINE('',#613,#612);
#615=CARTESIAN_POINT('',(32.05,12.9766151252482,15.8165412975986));
#616=VERTEX_POINT('',#615);
#617=EDGE_CURVE('E365',#616,#608,#614,.F.);
#618=ORIENTED_EDGE('',*,*,#617,.F.);
#619=DIRECTION('',(0.,-0.863308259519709,-0.504676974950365));
#620=VECTOR('',#619,1.);
#621=CARTESIAN_POINT('',(32.05,12.9766151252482,15.8165412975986));
#622=LINE('',#621,#620);
#623=EDGE_CURVE('E405',#616,#590,#622,.T.);
#624=ORIENTED_EDGE('',*,*,#623,.T.);
#625=EDGE_LOOP('',(#594,#602,#610,#618,#624));
#626=FACE_BOUND('',#625,.T.);
#627=ADVANCED_FACE('F1445',(#626),#584,.T.);
#628=CARTESIAN_POINT('',(38.7625,-1.75,3.09));
#629=DIRECTION('',(1.,0.,0.));
#630=DIRECTION('',(0.,1.,0.));
#631=AXIS2_PLACEMENT_3D('',#628,#629,#630);
#632=CYLINDRICAL_SURFACE('',#631,5.54);
#633=CARTESIAN_POINT('',(38.7625,-1.75,3.09));
#634=DIRECTION('',(1.,0.,0.));
#635=DIRECTION('',(0.,1.,0.));
#636=AXIS2_PLACEMENT_3D('',#633,#634,#635);
#637=CIRCLE('',#636,5.54);
#638=CARTESIAN_POINT('',(38.7625,-7.2834549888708,3.35921345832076));
#639=VERTEX_POINT('',#638);
#640=CARTESIAN_POINT('',(38.7625,-2.8772598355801,8.51410225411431));
#641=VERTEX_POINT('',#640);
#642=EDGE_CURVE('E483',#639,#641,#637,.F.);
#643=ORIENTED_EDGE('',*,*,#642,.T.);
#644=DIRECTION('',(-1.,0.,0.));
#645=VECTOR('',#644,1.);
#646=CARTESIAN_POINT('',(38.7625,-2.8772598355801,8.51410225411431));
#647=LINE('',#646,#645);
#648=CARTESIAN_POINT('',(38.63875,-2.8772598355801,8.51410225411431));
#649=VERTEX_POINT('',#648);
#650=EDGE_CURVE('E336',#641,#649,#647,.T.);
#651=ORIENTED_EDGE('',*,*,#650,.T.);
#652=CARTESIAN_POINT('',(38.63875,-1.75,3.09));
#653=DIRECTION('',(1.,0.,0.));
#654=DIRECTION('',(0.,1.,0.));
#655=AXIS2_PLACEMENT_3D('',#652,#653,#654);
#656=CIRCLE('',#655,5.54);
#657=CARTESIAN_POINT('',(38.63875,-7.2834549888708,3.35921345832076));
#658=VERTEX_POINT('',#657);
#659=EDGE_CURVE('E608',#658,#649,#656,.F.);
#660=ORIENTED_EDGE('',*,*,#659,.F.);
#661=DIRECTION('',(1.,0.,0.));
#662=VECTOR('',#661,1.);
#663=CARTESIAN_POINT('',(38.7625,-7.2834549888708,3.35921345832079));
#664=LINE('',#663,#662);
#665=EDGE_CURVE('E339',#658,#639,#664,.T.);
#666=ORIENTED_EDGE('',*,*,#665,.T.);
#667=EDGE_LOOP('',(#643,#651,#660,#666));
#668=FACE_BOUND('',#667,.T.);
#669=ADVANCED_FACE('F1066',(#668),#632,.T.);
#670=CARTESIAN_POINT('',(38.7625,-2.8772598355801,8.51410225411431));
#671=DIRECTION('',(0.,0.203476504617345,-0.979079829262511));
#672=DIRECTION('',(0.,-0.979079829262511,-0.203476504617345));
#673=AXIS2_PLACEMENT_3D('',#670,#671,#672);
#674=PLANE('',#673);
#675=ORIENTED_EDGE('',*,*,#650,.F.);
#676=DIRECTION('',(0.,0.979079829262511,0.203476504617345));
#677=VECTOR('',#676,1.);
#678=CARTESIAN_POINT('',(38.7625,-2.8772598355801,8.51410225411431));
#679=LINE('',#678,#677);
#680=CARTESIAN_POINT('',(38.7625,5.5926726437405,10.2743593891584));
#681=VERTEX_POINT('',#680);
#682=EDGE_CURVE('E485',#641,#681,#679,.T.);
#683=ORIENTED_EDGE('',*,*,#682,.T.);
#684=DIRECTION('',(-1.,0.,0.));
#685=VECTOR('',#684,1.);
#686=CARTESIAN_POINT('',(38.7625,5.5926726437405,10.2743593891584));
#687=LINE('',#686,#685);
#688=CARTESIAN_POINT('',(38.63875,5.5926726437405,10.2743593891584));
#689=VERTEX_POINT('',#688);
#690=EDGE_CURVE('E352',#681,#689,#687,.T.);
#691=ORIENTED_EDGE('',*,*,#690,.T.);
#692=DIRECTION('',(0.,0.979079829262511,0.203476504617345));
#693=VECTOR('',#692,1.);
#694=CARTESIAN_POINT('',(38.63875,-2.8772598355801,8.51410225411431));
#695=LINE('',#694,#693);
#696=EDGE_CURVE('E349',#649,#689,#695,.T.);
#697=ORIENTED_EDGE('',*,*,#696,.F.);
#698=EDGE_LOOP('',(#675,#683,#691,#697));
#699=FACE_BOUND('',#698,.T.);
#700=ADVANCED_FACE('F872',(#699),#674,.F.);
#701=CARTESIAN_POINT('',(-8.13875,15.5,0.));
#702=DIRECTION('',(1.,0.,0.));
#703=DIRECTION('',(0.,1.,0.));
#704=AXIS2_PLACEMENT_3D('',#701,#702,#703);
#705=PLANE('',#704);
#706=DIRECTION('',(0.,1.,0.));
#707=VECTOR('',#706,1.);
#708=CARTESIAN_POINT('',(-8.13875,15.5,3.35921345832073));
#709=LINE('',#708,#707);
#710=CARTESIAN_POINT('',(-8.13875,-8.2844566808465,3.35921345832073));
#711=VERTEX_POINT('',#710);
#712=EDGE_CURVE('E309',#711,#250,#709,.T.);
#713=ORIENTED_EDGE('',*,*,#712,.F.);
#714=CARTESIAN_POINT('',(-8.13875,-1.75,3.09));
#715=DIRECTION('',(1.,0.,0.));
#716=DIRECTION('',(0.,1.,0.));
#717=AXIS2_PLACEMENT_3D('',#714,#715,#716);
#718=CIRCLE('',#717,6.54);
#719=CARTESIAN_POINT('',(-8.13875,-3.0807363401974,9.49318208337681));
#720=VERTEX_POINT('',#719);
#721=EDGE_CURVE('E479',#720,#711,#718,.T.);
#722=ORIENTED_EDGE('',*,*,#721,.F.);
#723=DIRECTION('',(0.,0.979079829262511,0.203476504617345));
#724=VECTOR('',#723,1.);
#725=CARTESIAN_POINT('',(-8.13875,5.5926726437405,11.2957265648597));
#726=LINE('',#725,#724);
#727=CARTESIAN_POINT('',(-8.13875,5.5926726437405,11.2957265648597));
#728=VERTEX_POINT('',#727);
#729=EDGE_CURVE('E345',#728,#720,#726,.F.);
#730=ORIENTED_EDGE('',*,*,#729,.F.);
#731=DIRECTION('',(0.,0.,1.));
#732=VECTOR('',#731,1.);
#733=CARTESIAN_POINT('',(-8.13875,5.5926726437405,10.2743593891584));
#734=LINE('',#733,#732);
#735=EDGE_CURVE('E335',#728,#283,#734,.F.);
#736=ORIENTED_EDGE('',*,*,#735,.T.);
#737=ORIENTED_EDGE('',*,*,#297,.F.);
#738=ORIENTED_EDGE('',*,*,#260,.F.);
#739=EDGE_LOOP('',(#713,#722,#730,#736,#737,#738));
#740=FACE_BOUND('',#739,.T.);
#741=ADVANCED_FACE('F333',(#740),#705,.F.);
#742=CARTESIAN_POINT('',(38.63875,15.5,0.));
#743=DIRECTION('',(1.,0.,0.));
#744=DIRECTION('',(0.,1.,0.));
#745=AXIS2_PLACEMENT_3D('',#742,#743,#744);
#746=PLANE('',#745);
#747=DIRECTION('',(0.,0.979079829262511,0.203476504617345));
#748=VECTOR('',#747,1.);
#749=CARTESIAN_POINT('',(38.63875,5.5926726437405,11.2957265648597));
#750=LINE('',#749,#748);
#751=CARTESIAN_POINT('',(38.63875,-3.0807363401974,9.49318208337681));
#752=VERTEX_POINT('',#751);
#753=CARTESIAN_POINT('',(38.63875,5.5926726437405,11.2957265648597));
#754=VERTEX_POINT('',#753);
#755=EDGE_CURVE('E348',#752,#754,#750,.T.);
#756=ORIENTED_EDGE('',*,*,#755,.F.);
#757=CARTESIAN_POINT('',(38.63875,-1.75,3.09));
#758=DIRECTION('',(1.,0.,0.));
#759=DIRECTION('',(0.,1.,0.));
#760=AXIS2_PLACEMENT_3D('',#757,#758,#759);
#761=CIRCLE('',#760,6.54);
#762=CARTESIAN_POINT('',(38.63875,-8.2844566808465,3.35921345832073));
#763=VERTEX_POINT('',#762);
#764=EDGE_CURVE('E475',#763,#752,#761,.F.);
#765=ORIENTED_EDGE('',*,*,#764,.F.);
#766=DIRECTION('',(0.,1.,0.));
#767=VECTOR('',#766,1.);
#768=CARTESIAN_POINT('',(38.63875,15.5,3.35921345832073));
#769=LINE('',#768,#767);
#770=EDGE_CURVE('E332',#763,#658,#769,.T.);
#771=ORIENTED_EDGE('',*,*,#770,.T.);
#772=ORIENTED_EDGE('',*,*,#659,.T.);
#773=ORIENTED_EDGE('',*,*,#696,.T.);
#774=DIRECTION('',(0.,0.,1.));
#775=VECTOR('',#774,1.);
#776=CARTESIAN_POINT('',(38.63875,5.5926726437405,10.2743593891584));
#777=LINE('',#776,#775);
#778=EDGE_CURVE('E354',#689,#754,#777,.T.);
#779=ORIENTED_EDGE('',*,*,#778,.T.);
#780=EDGE_LOOP('',(#756,#765,#771,#772,#773,#779));
#781=FACE_BOUND('',#780,.T.);
#782=ADVANCED_FACE('F866',(#781),#746,.T.);
#783=CARTESIAN_POINT('',(38.63875,5.5926726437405,11.2957265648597));
#784=DIRECTION('',(0.,-0.203476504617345,0.979079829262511));
#785=DIRECTION('',(0.,0.979079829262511,0.203476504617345));
#786=AXIS2_PLACEMENT_3D('',#783,#784,#785);
#787=PLANE('',#786);
#788=ORIENTED_EDGE('',*,*,#755,.T.);
#789=DIRECTION('',(-1.,0.,0.));
#790=VECTOR('',#789,1.);
#791=CARTESIAN_POINT('',(38.7625,5.5926726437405,11.2957265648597));
#792=LINE('',#791,#790);
#793=EDGE_CURVE('E374',#754,#728,#792,.T.);
#794=ORIENTED_EDGE('',*,*,#793,.T.);
#795=ORIENTED_EDGE('',*,*,#729,.T.);
#796=DIRECTION('',(1.,0.,0.));
#797=VECTOR('',#796,1.);
#798=CARTESIAN_POINT('',(38.63875,-3.0807363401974,9.49318208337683));
#799=LINE('',#798,#797);
#800=EDGE_CURVE('E478',#752,#720,#799,.F.);
#801=ORIENTED_EDGE('',*,*,#800,.F.);
#802=EDGE_LOOP('',(#788,#794,#795,#801));
#803=FACE_BOUND('',#802,.T.);
#804=ADVANCED_FACE('F596',(#803),#787,.T.);
#805=CARTESIAN_POINT('',(0.,0.,7.675));
#806=DIRECTION('',(0.,0.,-1.));
#807=DIRECTION('',(1.,0.,0.));
#808=AXIS2_PLACEMENT_3D('',#805,#806,#807);
#809=CYLINDRICAL_SURFACE('',#808,5.25);
#810=ORIENTED_EDGE('',*,*,#48,.F.);
#811=ORIENTED_EDGE('',*,*,#89,.F.);
#812=DIRECTION('',(0.,0.,-1.));
#813=VECTOR('',#812,1.);
#814=CARTESIAN_POINT('',(0.,-5.25,7.675));
#815=LINE('',#814,#813);
#816=CARTESIAN_POINT('',(0.,-5.2499999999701,4.99999999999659));
#817=VERTEX_POINT('',#816);
#818=EDGE_CURVE('E838',#88,#817,#815,.T.);
#819=ORIENTED_EDGE('',*,*,#818,.T.);
#820=CARTESIAN_POINT('',(0.,0.,4.99999999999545));
#821=DIRECTION('',(0.,0.,1.));
#822=DIRECTION('',(0.,1.,0.));
#823=AXIS2_PLACEMENT_3D('',#820,#821,#822);
#824=CIRCLE('',#823,5.24999999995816);
#825=CARTESIAN_POINT('',(0.,5.24999999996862,4.99999999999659));
#826=VERTEX_POINT('',#825);
#827=EDGE_CURVE('E826',#817,#826,#824,.F.);
#828=ORIENTED_EDGE('',*,*,#827,.T.);
#829=DIRECTION('',(0.,0.,-1.));
#830=VECTOR('',#829,1.);
#831=CARTESIAN_POINT('',(0.,5.25,7.675));
#832=LINE('',#831,#830);
#833=EDGE_CURVE('E575',#826,#30,#832,.F.);
#834=ORIENTED_EDGE('',*,*,#833,.T.);
#835=EDGE_LOOP('',(#810,#811,#819,#828,#834));
#836=FACE_BOUND('',#835,.T.);
#837=ADVANCED_FACE('F591',(#836),#809,.F.);
#838=CARTESIAN_POINT('',(0.,0.,7.675));
#839=DIRECTION('',(0.,0.,-1.));
#840=DIRECTION('',(1.,0.,0.));
#841=AXIS2_PLACEMENT_3D('',#838,#839,#840);
#842=CYLINDRICAL_SURFACE('',#841,5.25);
#843=CARTESIAN_POINT('',(0.,0.,4.99999999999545));
#844=DIRECTION('',(0.,0.,1.));
#845=DIRECTION('',(0.,1.,0.));
#846=AXIS2_PLACEMENT_3D('',#843,#844,#845);
#847=CIRCLE('',#846,5.24999999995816);
#848=EDGE_CURVE('E828',#826,#817,#847,.F.);
#849=ORIENTED_EDGE('',*,*,#848,.T.);
#850=ORIENTED_EDGE('',*,*,#818,.F.);
#851=ORIENTED_EDGE('',*,*,#119,.F.);
#852=ORIENTED_EDGE('',*,*,#33,.F.);
#853=ORIENTED_EDGE('',*,*,#833,.F.);
#854=EDGE_LOOP('',(#849,#850,#851,#852,#853));
#855=FACE_BOUND('',#854,.T.);
#856=ADVANCED_FACE('F586',(#855),#842,.F.);
#857=CARTESIAN_POINT('',(30.5,0.,7.675));
#858=DIRECTION('',(0.,0.,-1.));
#859=DIRECTION('',(1.,0.,0.));
#860=AXIS2_PLACEMENT_3D('',#857,#858,#859);
#861=CYLINDRICAL_SURFACE('',#860,5.25);
#862=ORIENTED_EDGE('',*,*,#153,.F.);
#863=ORIENTED_EDGE('',*,*,#194,.F.);
#864=DIRECTION('',(0.,0.,-1.));
#865=VECTOR('',#864,1.);
#866=CARTESIAN_POINT('',(30.5,-5.25,7.675));
#867=LINE('',#866,#865);
#868=CARTESIAN_POINT('',(30.5,-5.2499999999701,4.99999999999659));
#869=VERTEX_POINT('',#868);
#870=EDGE_CURVE('E550',#193,#869,#867,.T.);
#871=ORIENTED_EDGE('',*,*,#870,.T.);
#872=CARTESIAN_POINT('',(30.5,0.,4.99999999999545));
#873=DIRECTION('',(0.,0.,1.));
#874=DIRECTION('',(0.,1.,0.));
#875=AXIS2_PLACEMENT_3D('',#872,#873,#874);
#876=CIRCLE('',#875,5.24999999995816);
#877=CARTESIAN_POINT('',(30.5,5.24999999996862,4.99999999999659));
#878=VERTEX_POINT('',#877);
#879=EDGE_CURVE('E808',#869,#878,#876,.F.);
#880=ORIENTED_EDGE('',*,*,#879,.T.);
#881=DIRECTION('',(0.,0.,-1.));
#882=VECTOR('',#881,1.);
#883=CARTESIAN_POINT('',(30.5,5.25,7.675));
#884=LINE('',#883,#882);
#885=EDGE_CURVE('E807',#878,#135,#884,.F.);
#886=ORIENTED_EDGE('',*,*,#885,.T.);
#887=EDGE_LOOP('',(#862,#863,#871,#880,#886));
#888=FACE_BOUND('',#887,.T.);
#889=ADVANCED_FACE('F583',(#888),#861,.F.);
#890=CARTESIAN_POINT('',(30.5,0.,7.675));
#891=DIRECTION('',(0.,0.,-1.));
#892=DIRECTION('',(1.,0.,0.));
#893=AXIS2_PLACEMENT_3D('',#890,#891,#892);
#894=CYLINDRICAL_SURFACE('',#893,5.25);
#895=CARTESIAN_POINT('',(30.5,0.,4.99999999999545));
#896=DIRECTION('',(0.,0.,1.));
#897=DIRECTION('',(0.,1.,0.));
#898=AXIS2_PLACEMENT_3D('',#895,#896,#897);
#899=CIRCLE('',#898,5.24999999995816);
#900=EDGE_CURVE('E810',#878,#869,#899,.F.);
#901=ORIENTED_EDGE('',*,*,#900,.T.);
#902=ORIENTED_EDGE('',*,*,#870,.F.);
#903=ORIENTED_EDGE('',*,*,#224,.F.);
#904=ORIENTED_EDGE('',*,*,#138,.F.);
#905=ORIENTED_EDGE('',*,*,#885,.F.);
#906=EDGE_LOOP('',(#901,#902,#903,#904,#905));
#907=FACE_BOUND('',#906,.T.);
#908=ADVANCED_FACE('F553',(#907),#894,.F.);
#909=CARTESIAN_POINT('',(-8.2625,15.5,0.));
#910=DIRECTION('',(1.,0.,0.));
#911=DIRECTION('',(0.,1.,0.));
#912=AXIS2_PLACEMENT_3D('',#909,#910,#911);
#913=PLANE('',#912);
#914=ORIENTED_EDGE('',*,*,#290,.T.);
#915=DIRECTION('',(0.,0.,1.));
#916=VECTOR('',#915,1.);
#917=CARTESIAN_POINT('',(-8.2625,5.5926726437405,10.2743593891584));
#918=LINE('',#917,#916);
#919=CARTESIAN_POINT('',(-8.2625,5.59267264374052,11.5));
#920=VERTEX_POINT('',#919);
#921=EDGE_CURVE('E782',#281,#920,#918,.T.);
#922=ORIENTED_EDGE('',*,*,#921,.T.);
#923=DIRECTION('',(0.,0.979079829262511,0.203476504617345));
#924=VECTOR('',#923,1.);
#925=CARTESIAN_POINT('',(-8.2625,5.59267264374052,11.5));
#926=LINE('',#925,#924);
#927=CARTESIAN_POINT('',(-8.2625,-3.1214316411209,9.68899804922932));
#928=VERTEX_POINT('',#927);
#929=EDGE_CURVE('E474',#928,#920,#926,.T.);
#930=ORIENTED_EDGE('',*,*,#929,.F.);
#931=CARTESIAN_POINT('',(-8.2625,-1.75,3.09));
#932=DIRECTION('',(1.,0.,0.));
#933=DIRECTION('',(0.,1.,0.));
#934=AXIS2_PLACEMENT_3D('',#931,#932,#933);
#935=CIRCLE('',#934,6.74);
#936=CARTESIAN_POINT('',(-8.2625,-8.4846213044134,3.35921345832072));
#937=VERTEX_POINT('',#936);
#938=EDGE_CURVE('E471',#937,#928,#935,.F.);
#939=ORIENTED_EDGE('',*,*,#938,.F.);
#940=DIRECTION('',(0.,1.,0.));
#941=VECTOR('',#940,1.);
#942=CARTESIAN_POINT('',(-8.2625,15.5,3.35921345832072));
#943=LINE('',#942,#941);
#944=EDGE_CURVE('E541',#937,#240,#943,.T.);
#945=ORIENTED_EDGE('',*,*,#944,.T.);
#946=ORIENTED_EDGE('',*,*,#243,.T.);
#947=EDGE_LOOP('',(#914,#922,#930,#939,#945,#946));
#948=FACE_BOUND('',#947,.T.);
#949=ADVANCED_FACE('F772',(#948),#913,.T.);
#950=CARTESIAN_POINT('',(-1.35,15.5,0.));
#951=DIRECTION('',(1.,0.,0.));
#952=DIRECTION('',(0.,1.,0.));
#953=AXIS2_PLACEMENT_3D('',#950,#951,#952);
#954=PLANE('',#953);
#955=ORIENTED_EDGE('',*,*,#463,.F.);
#956=CARTESIAN_POINT('',(-1.35,15.5,11.5));
#957=DIRECTION('',(1.,0.,0.));
#958=DIRECTION('',(0.,1.,0.));
#959=AXIS2_PLACEMENT_3D('',#956,#957,#958);
#960=CIRCLE('',#959,5.);
#961=CARTESIAN_POINT('',(-1.35,18.5073278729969,7.5055064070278));
#962=VERTEX_POINT('',#961);
#963=EDGE_CURVE('E390',#962,#454,#960,.T.);
#964=ORIENTED_EDGE('',*,*,#963,.F.);
#965=DIRECTION('',(0.,-0.798898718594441,-0.601465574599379));
#966=VECTOR('',#965,1.);
#967=CARTESIAN_POINT('',(-1.35,13.,3.35921345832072));
#968=LINE('',#967,#966);
#969=CARTESIAN_POINT('',(-1.35,13.,3.35921345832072));
#970=VERTEX_POINT('',#969);
#971=EDGE_CURVE('E911',#970,#962,#968,.F.);
#972=ORIENTED_EDGE('',*,*,#971,.F.);
#973=CARTESIAN_POINT('',(-1.35,-8.87,-9.1));
#974=DIRECTION('',(1.,0.,0.));
#975=DIRECTION('',(0.,1.,0.));
#976=AXIS2_PLACEMENT_3D('',#973,#974,#975);
#977=CIRCLE('',#976,25.17);
#978=EDGE_CURVE('E466',#462,#970,#977,.F.);
#979=ORIENTED_EDGE('',*,*,#978,.F.);
#980=EDGE_LOOP('',(#955,#964,#972,#979));
#981=FACE_BOUND('',#980,.T.);
#982=ORIENTED_EDGE('',*,*,#333,.F.);
#983=ORIENTED_EDGE('',*,*,#354,.F.);
#984=EDGE_LOOP('',(#982,#983));
#985=FACE_BOUND('',#984,.T.);
#986=ADVANCED_FACE('F769',(#981,#985),#954,.F.);
#987=CARTESIAN_POINT('',(6.8,15.5,11.5));
#988=DIRECTION('',(1.,0.,0.));
#989=DIRECTION('',(0.,1.,0.));
#990=AXIS2_PLACEMENT_3D('',#987,#988,#989);
#991=CYLINDRICAL_SURFACE('',#990,5.);
#992=CARTESIAN_POINT('',(6.8,15.5,11.5));
#993=DIRECTION('',(1.,0.,0.));
#994=DIRECTION('',(0.,1.,0.));
#995=AXIS2_PLACEMENT_3D('',#992,#993,#994);
#996=CIRCLE('',#995,5.);
#997=CARTESIAN_POINT('',(6.8,18.5073278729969,7.5055064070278));
#998=VERTEX_POINT('',#997);
#999=EDGE_CURVE('E389',#998,#444,#996,.T.);
#1000=ORIENTED_EDGE('',*,*,#999,.F.);
#1001=DIRECTION('',(-1.,0.,0.));
#1002=VECTOR('',#1001,1.);
#1003=CARTESIAN_POINT('',(6.8,18.5073278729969,7.5055064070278));
#1004=LINE('',#1003,#1002);
#1005=EDGE_CURVE('E908',#962,#998,#1004,.F.);
#1006=ORIENTED_EDGE('',*,*,#1005,.F.);
#1007=ORIENTED_EDGE('',*,*,#963,.T.);
#1008=ORIENTED_EDGE('',*,*,#455,.T.);
#1009=EDGE_LOOP('',(#1000,#1006,#1007,#1008));
#1010=FACE_BOUND('',#1009,.T.);
#1011=ADVANCED_FACE('F765',(#1010),#991,.T.);
#1012=CARTESIAN_POINT('',(6.8,15.5,0.));
#1013=DIRECTION('',(1.,0.,0.));
#1014=DIRECTION('',(0.,1.,0.));
#1015=AXIS2_PLACEMENT_3D('',#1012,#1013,#1014);
#1016=PLANE('',#1015);
#1017=ORIENTED_EDGE('',*,*,#316,.T.);
#1018=ORIENTED_EDGE('',*,*,#362,.T.);
#1019=EDGE_LOOP('',(#1017,#1018));
#1020=FACE_BOUND('',#1019,.T.);
#1021=ORIENTED_EDGE('',*,*,#999,.T.);
#1022=ORIENTED_EDGE('',*,*,#447,.T.);
#1023=CARTESIAN_POINT('',(6.8,-8.87,-9.1));
#1024=DIRECTION('',(1.,0.,0.));
#1025=DIRECTION('',(0.,1.,0.));
#1026=AXIS2_PLACEMENT_3D('',#1023,#1024,#1025);
#1027=CIRCLE('',#1026,25.17);
#1028=CARTESIAN_POINT('',(6.8,13.,3.35921345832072));
#1029=VERTEX_POINT('',#1028);
#1030=EDGE_CURVE('E462',#1029,#446,#1027,.T.);
#1031=ORIENTED_EDGE('',*,*,#1030,.F.);
#1032=DIRECTION('',(0.,-0.798898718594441,-0.601465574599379));
#1033=VECTOR('',#1032,1.);
#1034=CARTESIAN_POINT('',(6.8,13.,3.35921345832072));
#1035=LINE('',#1034,#1033);
#1036=EDGE_CURVE('E465',#998,#1029,#1035,.T.);
#1037=ORIENTED_EDGE('',*,*,#1036,.F.);
#1038=EDGE_LOOP('',(#1021,#1022,#1031,#1037));
#1039=FACE_BOUND('',#1038,.T.);
#1040=ADVANCED_FACE('F761',(#1020,#1039),#1016,.T.);
#1041=CARTESIAN_POINT('',(15.35,15.5,0.));
#1042=DIRECTION('',(1.,0.,0.));
#1043=DIRECTION('',(0.,1.,0.));
#1044=AXIS2_PLACEMENT_3D('',#1041,#1042,#1043);
#1045=PLANE('',#1044);
#1046=ORIENTED_EDGE('',*,*,#420,.F.);
#1047=ORIENTED_EDGE('',*,*,#399,.F.);
#1048=EDGE_LOOP('',(#1046,#1047));
#1049=FACE_BOUND('',#1048,.T.);
#1050=ORIENTED_EDGE('',*,*,#487,.F.);
#1051=CARTESIAN_POINT('',(15.35,15.5,11.5));
#1052=DIRECTION('',(-1.,0.,0.));
#1053=DIRECTION('',(0.,-1.,0.));
#1054=AXIS2_PLACEMENT_3D('',#1051,#1052,#1053);
#1055=CIRCLE('',#1054,5.);
#1056=CARTESIAN_POINT('',(15.35,18.5073278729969,7.5055064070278));
#1057=VERTEX_POINT('',#1056);
#1058=EDGE_CURVE('E380',#1057,#484,#1055,.F.);
#1059=ORIENTED_EDGE('',*,*,#1058,.F.);
#1060=DIRECTION('',(0.,-0.798898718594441,-0.601465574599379));
#1061=VECTOR('',#1060,1.);
#1062=CARTESIAN_POINT('',(15.35,18.5073278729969,7.5055064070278));
#1063=LINE('',#1062,#1061);
#1064=CARTESIAN_POINT('',(15.35,13.,3.35921345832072));
#1065=VERTEX_POINT('',#1064);
#1066=EDGE_CURVE('E903',#1065,#1057,#1063,.F.);
#1067=ORIENTED_EDGE('',*,*,#1066,.F.);
#1068=CARTESIAN_POINT('',(15.35,-8.87,-9.1));
#1069=DIRECTION('',(1.,0.,0.));
#1070=DIRECTION('',(0.,1.,0.));
#1071=AXIS2_PLACEMENT_3D('',#1068,#1069,#1070);
#1072=CIRCLE('',#1071,25.17);
#1073=EDGE_CURVE('E457',#486,#1065,#1072,.F.);
#1074=ORIENTED_EDGE('',*,*,#1073,.F.);
#1075=EDGE_LOOP('',(#1050,#1059,#1067,#1074));
#1076=FACE_BOUND('',#1075,.T.);
#1077=ADVANCED_FACE('F757',(#1049,#1076),#1045,.F.);
#1078=CARTESIAN_POINT('',(15.35,15.5,11.5));
#1079=DIRECTION('',(-1.,0.,0.));
#1080=DIRECTION('',(0.,-1.,0.));
#1081=AXIS2_PLACEMENT_3D('',#1078,#1079,#1080);
#1082=CYLINDRICAL_SURFACE('',#1081,5.);
#1083=ORIENTED_EDGE('',*,*,#1058,.T.);
#1084=ORIENTED_EDGE('',*,*,#509,.T.);
#1085=CARTESIAN_POINT('',(23.5,15.5,11.5));
#1086=DIRECTION('',(-1.,0.,0.));
#1087=DIRECTION('',(0.,-1.,0.));
#1088=AXIS2_PLACEMENT_3D('',#1085,#1086,#1087);
#1089=CIRCLE('',#1088,5.);
#1090=CARTESIAN_POINT('',(23.5,18.5073278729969,7.5055064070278));
#1091=VERTEX_POINT('',#1090);
#1092=EDGE_CURVE('E504',#1091,#502,#1089,.F.);
#1093=ORIENTED_EDGE('',*,*,#1092,.F.);
#1094=DIRECTION('',(-1.,0.,0.));
#1095=VECTOR('',#1094,1.);
#1096=CARTESIAN_POINT('',(15.35,18.5073278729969,7.5055064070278));
#1097=LINE('',#1096,#1095);
#1098=EDGE_CURVE('E456',#1057,#1091,#1097,.F.);
#1099=ORIENTED_EDGE('',*,*,#1098,.F.);
#1100=EDGE_LOOP('',(#1083,#1084,#1093,#1099));
#1101=FACE_BOUND('',#1100,.T.);
#1102=ADVANCED_FACE('F753',(#1101),#1082,.T.);
#1103=CARTESIAN_POINT('',(23.5,15.5,0.));
#1104=DIRECTION('',(1.,0.,0.));
#1105=DIRECTION('',(0.,1.,0.));
#1106=AXIS2_PLACEMENT_3D('',#1103,#1104,#1105);
#1107=PLANE('',#1106);
#1108=ORIENTED_EDGE('',*,*,#1092,.T.);
#1109=ORIENTED_EDGE('',*,*,#503,.T.);
#1110=CARTESIAN_POINT('',(23.5,-8.87,-9.1));
#1111=DIRECTION('',(1.,0.,0.));
#1112=DIRECTION('',(0.,1.,0.));
#1113=AXIS2_PLACEMENT_3D('',#1110,#1111,#1112);
#1114=CIRCLE('',#1113,25.17);
#1115=CARTESIAN_POINT('',(23.5,13.,3.35921345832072));
#1116=VERTEX_POINT('',#1115);
#1117=EDGE_CURVE('E449',#1116,#494,#1114,.T.);
#1118=ORIENTED_EDGE('',*,*,#1117,.F.);
#1119=DIRECTION('',(0.,-0.798898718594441,-0.601465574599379));
#1120=VECTOR('',#1119,1.);
#1121=CARTESIAN_POINT('',(23.5,18.5073278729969,7.5055064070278));
#1122=LINE('',#1121,#1120);
#1123=EDGE_CURVE('E460',#1091,#1116,#1122,.T.);
#1124=ORIENTED_EDGE('',*,*,#1123,.F.);
#1125=EDGE_LOOP('',(#1108,#1109,#1118,#1124));
#1126=FACE_BOUND('',#1125,.T.);
#1127=ORIENTED_EDGE('',*,*,#382,.T.);
#1128=ORIENTED_EDGE('',*,*,#428,.T.);
#1129=EDGE_LOOP('',(#1127,#1128));
#1130=FACE_BOUND('',#1129,.T.);
#1131=ADVANCED_FACE('F749',(#1126,#1130),#1107,.T.);
#1132=CARTESIAN_POINT('',(38.7625,5.5926726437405,10.2743593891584));
#1133=DIRECTION('',(0.,1.,0.));
#1134=DIRECTION('',(-1.,0.,0.));
#1135=AXIS2_PLACEMENT_3D('',#1132,#1133,#1134);
#1136=PLANE('',#1135);
#1137=ORIENTED_EDGE('',*,*,#793,.F.);
#1138=ORIENTED_EDGE('',*,*,#778,.F.);
#1139=ORIENTED_EDGE('',*,*,#690,.F.);
#1140=DIRECTION('',(0.,0.,1.));
#1141=VECTOR('',#1140,1.);
#1142=CARTESIAN_POINT('',(38.7625,5.5926726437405,0.));
#1143=LINE('',#1142,#1141);
#1144=EDGE_CURVE('E482',#681,#592,#1143,.T.);
#1145=ORIENTED_EDGE('',*,*,#1144,.T.);
#1146=ORIENTED_EDGE('',*,*,#593,.F.);
#1147=DIRECTION('',(1.,0.,0.));
#1148=VECTOR('',#1147,1.);
#1149=CARTESIAN_POINT('',(40.,5.59267264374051,11.5));
#1150=LINE('',#1149,#1148);
#1151=EDGE_CURVE('E452',#494,#590,#1150,.T.);
#1152=ORIENTED_EDGE('',*,*,#1151,.F.);
#1153=ORIENTED_EDGE('',*,*,#495,.F.);
#1154=DIRECTION('',(1.,0.,0.));
#1155=VECTOR('',#1154,1.);
#1156=CARTESIAN_POINT('',(40.,5.59267264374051,11.5));
#1157=LINE('',#1156,#1155);
#1158=EDGE_CURVE('E461',#446,#486,#1157,.T.);
#1159=ORIENTED_EDGE('',*,*,#1158,.F.);
#1160=ORIENTED_EDGE('',*,*,#469,.F.);
#1161=DIRECTION('',(1.,0.,0.));
#1162=VECTOR('',#1161,1.);
#1163=CARTESIAN_POINT('',(40.,5.59267264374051,11.5));
#1164=LINE('',#1163,#1162);
#1165=EDGE_CURVE('E790',#920,#462,#1164,.T.);
#1166=ORIENTED_EDGE('',*,*,#1165,.F.);
#1167=ORIENTED_EDGE('',*,*,#921,.F.);
#1168=ORIENTED_EDGE('',*,*,#284,.T.);
#1169=ORIENTED_EDGE('',*,*,#735,.F.);
#1170=EDGE_LOOP('',(#1137,#1138,#1139,#1145,#1146,#1152,#1153,#1159,#1160,#1166,#1167,#1168,#1169));
#1171=FACE_BOUND('',#1170,.T.);
#1172=ADVANCED_FACE('F745',(#1171),#1136,.F.);
#1173=CARTESIAN_POINT('',(32.05,15.5,0.));
#1174=DIRECTION('',(1.,0.,0.));
#1175=DIRECTION('',(0.,1.,0.));
#1176=AXIS2_PLACEMENT_3D('',#1173,#1174,#1175);
#1177=PLANE('',#1176);
#1178=ORIENTED_EDGE('',*,*,#566,.F.);
#1179=ORIENTED_EDGE('',*,*,#545,.F.);
#1180=EDGE_LOOP('',(#1178,#1179));
#1181=FACE_BOUND('',#1180,.T.);
#1182=ORIENTED_EDGE('',*,*,#623,.F.);
#1183=CARTESIAN_POINT('',(32.05,15.5,11.5));
#1184=DIRECTION('',(-1.,0.,0.));
#1185=DIRECTION('',(0.,-1.,0.));
#1186=AXIS2_PLACEMENT_3D('',#1183,#1184,#1185);
#1187=CIRCLE('',#1186,5.);
#1188=CARTESIAN_POINT('',(32.05,18.5073278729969,7.5055064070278));
#1189=VERTEX_POINT('',#1188);
#1190=EDGE_CURVE('E368',#1189,#616,#1187,.F.);
#1191=ORIENTED_EDGE('',*,*,#1190,.F.);
#1192=DIRECTION('',(0.,-0.798898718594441,-0.601465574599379));
#1193=VECTOR('',#1192,1.);
#1194=CARTESIAN_POINT('',(32.05,18.5073278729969,7.5055064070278));
#1195=LINE('',#1194,#1193);
#1196=CARTESIAN_POINT('',(32.05,13.,3.35921345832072));
#1197=VERTEX_POINT('',#1196);
#1198=EDGE_CURVE('E890',#1197,#1189,#1195,.F.);
#1199=ORIENTED_EDGE('',*,*,#1198,.F.);
#1200=CARTESIAN_POINT('',(32.05,-8.87,-9.1));
#1201=DIRECTION('',(1.,0.,0.));
#1202=DIRECTION('',(0.,1.,0.));
#1203=AXIS2_PLACEMENT_3D('',#1200,#1201,#1202);
#1204=CIRCLE('',#1203,25.17);
#1205=EDGE_CURVE('E453',#590,#1197,#1204,.F.);
#1206=ORIENTED_EDGE('',*,*,#1205,.F.);
#1207=EDGE_LOOP('',(#1182,#1191,#1199,#1206));
#1208=FACE_BOUND('',#1207,.T.);
#1209=ADVANCED_FACE('F741',(#1181,#1208),#1177,.F.);
#1210=CARTESIAN_POINT('',(32.05,15.5,11.5));
#1211=DIRECTION('',(-1.,0.,0.));
#1212=DIRECTION('',(0.,-1.,0.));
#1213=AXIS2_PLACEMENT_3D('',#1210,#1211,#1212);
#1214=CYLINDRICAL_SURFACE('',#1213,5.);
#1215=ORIENTED_EDGE('',*,*,#1190,.T.);
#1216=ORIENTED_EDGE('',*,*,#617,.T.);
#1217=CARTESIAN_POINT('',(39.35,15.5,11.5));
#1218=DIRECTION('',(-1.,0.,0.));
#1219=DIRECTION('',(0.,-1.,0.));
#1220=AXIS2_PLACEMENT_3D('',#1217,#1218,#1219);
#1221=CIRCLE('',#1220,5.);
#1222=CARTESIAN_POINT('',(39.35,18.5073278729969,7.5055064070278));
#1223=VERTEX_POINT('',#1222);
#1224=EDGE_CURVE('E487',#1223,#608,#1221,.F.);
#1225=ORIENTED_EDGE('',*,*,#1224,.F.);
#1226=DIRECTION('',(-1.,0.,0.));
#1227=VECTOR('',#1226,1.);
#1228=CARTESIAN_POINT('',(32.05,18.5073278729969,7.5055064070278));
#1229=LINE('',#1228,#1227);
#1230=EDGE_CURVE('E448',#1189,#1223,#1229,.F.);
#1231=ORIENTED_EDGE('',*,*,#1230,.F.);
#1232=EDGE_LOOP('',(#1215,#1216,#1225,#1231));
#1233=FACE_BOUND('',#1232,.T.);
#1234=ADVANCED_FACE('F737',(#1233),#1214,.T.);
#1235=CARTESIAN_POINT('',(39.35,15.5,0.));
#1236=DIRECTION('',(1.,0.,0.));
#1237=DIRECTION('',(0.,1.,0.));
#1238=AXIS2_PLACEMENT_3D('',#1235,#1236,#1237);
#1239=PLANE('',#1238);
#1240=ORIENTED_EDGE('',*,*,#1224,.T.);
#1241=ORIENTED_EDGE('',*,*,#609,.T.);
#1242=CARTESIAN_POINT('',(39.35,-8.87,-9.1));
#1243=DIRECTION('',(1.,0.,0.));
#1244=DIRECTION('',(0.,1.,0.));
#1245=AXIS2_PLACEMENT_3D('',#1242,#1243,#1244);
#1246=CIRCLE('',#1245,25.17);
#1247=CARTESIAN_POINT('',(39.35,13.,3.35921345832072));
#1248=VERTEX_POINT('',#1247);
#1249=EDGE_CURVE('E444',#1248,#600,#1246,.T.);
#1250=ORIENTED_EDGE('',*,*,#1249,.F.);
#1251=DIRECTION('',(0.,-0.798898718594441,-0.601465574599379));
#1252=VECTOR('',#1251,1.);
#1253=CARTESIAN_POINT('',(39.35,18.5073278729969,7.5055064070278));
#1254=LINE('',#1253,#1252);
#1255=EDGE_CURVE('E894',#1223,#1248,#1254,.T.);
#1256=ORIENTED_EDGE('',*,*,#1255,.F.);
#1257=EDGE_LOOP('',(#1240,#1241,#1250,#1256));
#1258=FACE_BOUND('',#1257,.T.);
#1259=ORIENTED_EDGE('',*,*,#528,.T.);
#1260=ORIENTED_EDGE('',*,*,#574,.T.);
#1261=EDGE_LOOP('',(#1259,#1260));
#1262=FACE_BOUND('',#1261,.T.);
#1263=ADVANCED_FACE('F733',(#1258,#1262),#1239,.T.);
#1264=CARTESIAN_POINT('',(38.7625,15.5,0.));
#1265=DIRECTION('',(1.,0.,0.));
#1266=DIRECTION('',(0.,1.,0.));
#1267=AXIS2_PLACEMENT_3D('',#1264,#1265,#1266);
#1268=PLANE('',#1267);
#1269=ORIENTED_EDGE('',*,*,#1144,.F.);
#1270=ORIENTED_EDGE('',*,*,#682,.F.);
#1271=ORIENTED_EDGE('',*,*,#642,.F.);
#1272=DIRECTION('',(0.,1.,0.));
#1273=VECTOR('',#1272,1.);
#1274=CARTESIAN_POINT('',(38.7625,15.5,3.35921345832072));
#1275=LINE('',#1274,#1273);
#1276=CARTESIAN_POINT('',(38.7625,-8.4846213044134,3.35921345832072));
#1277=VERTEX_POINT('',#1276);
#1278=EDGE_CURVE('E486',#1277,#639,#1275,.T.);
#1279=ORIENTED_EDGE('',*,*,#1278,.F.);
#1280=CARTESIAN_POINT('',(38.7625,-1.75,3.09));
#1281=DIRECTION('',(1.,0.,0.));
#1282=DIRECTION('',(0.,1.,0.));
#1283=AXIS2_PLACEMENT_3D('',#1280,#1281,#1282);
#1284=CIRCLE('',#1283,6.74);
#1285=CARTESIAN_POINT('',(38.7625,-3.1214316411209,9.68899804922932));
#1286=VERTEX_POINT('',#1285);
#1287=EDGE_CURVE('E439',#1286,#1277,#1284,.T.);
#1288=ORIENTED_EDGE('',*,*,#1287,.F.);
#1289=DIRECTION('',(0.,0.979079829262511,0.203476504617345));
#1290=VECTOR('',#1289,1.);
#1291=CARTESIAN_POINT('',(38.7625,5.59267264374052,11.5));
#1292=LINE('',#1291,#1290);
#1293=EDGE_CURVE('E447',#592,#1286,#1292,.F.);
#1294=ORIENTED_EDGE('',*,*,#1293,.F.);
#1295=EDGE_LOOP('',(#1269,#1270,#1271,#1279,#1288,#1294));
#1296=FACE_BOUND('',#1295,.T.);
#1297=ADVANCED_FACE('F729',(#1296),#1268,.F.);
#1298=CARTESIAN_POINT('',(38.63875,-1.75,3.09));
#1299=DIRECTION('',(1.,0.,0.));
#1300=DIRECTION('',(0.,1.,0.));
#1301=AXIS2_PLACEMENT_3D('',#1298,#1299,#1300);
#1302=CYLINDRICAL_SURFACE('',#1301,6.54);
#1303=ORIENTED_EDGE('',*,*,#764,.T.);
#1304=ORIENTED_EDGE('',*,*,#800,.T.);
#1305=ORIENTED_EDGE('',*,*,#721,.T.);
#1306=DIRECTION('',(-1.,0.,0.));
#1307=VECTOR('',#1306,1.);
#1308=CARTESIAN_POINT('',(40.,-8.2844566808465,3.35921345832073));
#1309=LINE('',#1308,#1307);
#1310=EDGE_CURVE('E850',#763,#711,#1309,.T.);
#1311=ORIENTED_EDGE('',*,*,#1310,.F.);
#1312=EDGE_LOOP('',(#1303,#1304,#1305,#1311));
#1313=FACE_BOUND('',#1312,.T.);
#1314=ADVANCED_FACE('F725',(#1313),#1302,.T.);
#1315=CARTESIAN_POINT('',(0.,0.,4.99999999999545));
#1316=DIRECTION('',(0.,0.,1.));
#1317=DIRECTION('',(-1.,0.,0.));
#1318=AXIS2_PLACEMENT_3D('',#1315,#1316,#1317);
#1319=CONICAL_SURFACE('',#1318,5.24999999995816,0.896055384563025);
#1320=ORIENTED_EDGE('',*,*,#827,.F.);
#1321=DIRECTION('',(0.,0.78086880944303,-0.624695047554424));
#1322=VECTOR('',#1321,1.);
#1323=CARTESIAN_POINT('',(-6.11004302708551E-11,-499015.5,399213.2));
#1324=LINE('',#1323,#1322);
#1325=CARTESIAN_POINT('',(0.,-2.7500000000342,3.0000000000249));
#1326=VERTEX_POINT('',#1325);
#1327=EDGE_CURVE('E833',#817,#1326,#1324,.T.);
#1328=ORIENTED_EDGE('',*,*,#1327,.T.);
#1329=CARTESIAN_POINT('',(0.,0.,3.));
#1330=DIRECTION('',(0.,0.,-1.));
#1331=DIRECTION('',(1.,0.,0.));
#1332=AXIS2_PLACEMENT_3D('',#1329,#1330,#1331);
#1333=CIRCLE('',#1332,2.75);
#1334=CARTESIAN_POINT('',(0.,2.75000000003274,3.0000000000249));
#1335=VERTEX_POINT('',#1334);
#1336=EDGE_CURVE('E852',#1326,#1335,#1333,.T.);
#1337=ORIENTED_EDGE('',*,*,#1336,.T.);
#1338=DIRECTION('',(0.,-0.78086880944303,-0.624695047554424));
#1339=VECTOR('',#1338,1.);
#1340=CARTESIAN_POINT('',(0.,499015.5,399213.2));
#1341=LINE('',#1340,#1339);
#1342=EDGE_CURVE('E811',#1335,#826,#1341,.F.);
#1343=ORIENTED_EDGE('',*,*,#1342,.T.);
#1344=EDGE_LOOP('',(#1320,#1328,#1337,#1343));
#1345=FACE_BOUND('',#1344,.T.);
#1346=ADVANCED_FACE('F721',(#1345),#1319,.F.);
#1347=CARTESIAN_POINT('',(0.,0.,4.99999999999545));
#1348=DIRECTION('',(0.,0.,1.));
#1349=DIRECTION('',(-1.,0.,0.));
#1350=AXIS2_PLACEMENT_3D('',#1347,#1348,#1349);
#1351=CONICAL_SURFACE('',#1350,5.24999999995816,0.896055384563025);
#1352=CARTESIAN_POINT('',(0.,0.,3.));
#1353=DIRECTION('',(0.,0.,-1.));
#1354=DIRECTION('',(1.,0.,0.));
#1355=AXIS2_PLACEMENT_3D('',#1352,#1353,#1354);
#1356=CIRCLE('',#1355,2.75);
#1357=EDGE_CURVE('E943',#1335,#1326,#1356,.T.);
#1358=ORIENTED_EDGE('',*,*,#1357,.T.);
#1359=ORIENTED_EDGE('',*,*,#1327,.F.);
#1360=ORIENTED_EDGE('',*,*,#848,.F.);
#1361=ORIENTED_EDGE('',*,*,#1342,.F.);
#1362=EDGE_LOOP('',(#1358,#1359,#1360,#1361));
#1363=FACE_BOUND('',#1362,.T.);
#1364=ADVANCED_FACE('F717',(#1363),#1351,.F.);
#1365=CARTESIAN_POINT('',(30.5,0.,4.99999999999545));
#1366=DIRECTION('',(0.,0.,1.));
#1367=DIRECTION('',(-1.,0.,0.));
#1368=AXIS2_PLACEMENT_3D('',#1365,#1366,#1367);
#1369=CONICAL_SURFACE('',#1368,5.24999999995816,0.896055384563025);
#1370=ORIENTED_EDGE('',*,*,#879,.F.);
#1371=DIRECTION('',(0.,0.78086880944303,-0.624695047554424));
#1372=VECTOR('',#1371,1.);
#1373=CARTESIAN_POINT('',(30.4999999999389,-499015.5,399213.2));
#1374=LINE('',#1373,#1372);
#1375=CARTESIAN_POINT('',(30.5,-2.7500000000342,3.0000000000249));
#1376=VERTEX_POINT('',#1375);
#1377=EDGE_CURVE('E816',#869,#1376,#1374,.T.);
#1378=ORIENTED_EDGE('',*,*,#1377,.T.);
#1379=CARTESIAN_POINT('',(30.5,0.,3.));
#1380=DIRECTION('',(0.,0.,-1.));
#1381=DIRECTION('',(1.,0.,0.));
#1382=AXIS2_PLACEMENT_3D('',#1379,#1380,#1381);
#1383=CIRCLE('',#1382,2.75);
#1384=CARTESIAN_POINT('',(30.5,2.75000000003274,3.0000000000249));
#1385=VERTEX_POINT('',#1384);
#1386=EDGE_CURVE('E924',#1376,#1385,#1383,.T.);
#1387=ORIENTED_EDGE('',*,*,#1386,.T.);
#1388=DIRECTION('',(0.,-0.78086880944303,-0.624695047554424));
#1389=VECTOR('',#1388,1.);
#1390=CARTESIAN_POINT('',(30.5,499015.5,399213.2));
#1391=LINE('',#1390,#1389);
#1392=EDGE_CURVE('E914',#1385,#878,#1391,.F.);
#1393=ORIENTED_EDGE('',*,*,#1392,.T.);
#1394=EDGE_LOOP('',(#1370,#1378,#1387,#1393));
#1395=FACE_BOUND('',#1394,.T.);
#1396=ADVANCED_FACE('F713',(#1395),#1369,.F.);
#1397=CARTESIAN_POINT('',(30.5,0.,4.99999999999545));
#1398=DIRECTION('',(0.,0.,1.));
#1399=DIRECTION('',(-1.,0.,0.));
#1400=AXIS2_PLACEMENT_3D('',#1397,#1398,#1399);
#1401=CONICAL_SURFACE('',#1400,5.24999999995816,0.896055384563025);
#1402=CARTESIAN_POINT('',(30.5,0.,3.));
#1403=DIRECTION('',(0.,0.,-1.));
#1404=DIRECTION('',(1.,0.,0.));
#1405=AXIS2_PLACEMENT_3D('',#1402,#1403,#1404);
#1406=CIRCLE('',#1405,2.75);
#1407=EDGE_CURVE('E926',#1385,#1376,#1406,.T.);
#1408=ORIENTED_EDGE('',*,*,#1407,.T.);
#1409=ORIENTED_EDGE('',*,*,#1377,.F.);
#1410=ORIENTED_EDGE('',*,*,#900,.F.);
#1411=ORIENTED_EDGE('',*,*,#1392,.F.);
#1412=EDGE_LOOP('',(#1408,#1409,#1410,#1411));
#1413=FACE_BOUND('',#1412,.T.);
#1414=ADVANCED_FACE('F709',(#1413),#1401,.F.);
#1415=CARTESIAN_POINT('',(40.,5.59267264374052,11.5));
#1416=DIRECTION('',(0.,-0.203476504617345,0.979079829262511));
#1417=DIRECTION('',(0.,0.979079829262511,0.203476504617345));
#1418=AXIS2_PLACEMENT_3D('',#1415,#1416,#1417);
#1419=PLANE('',#1418);
#1420=DIRECTION('',(0.,-0.979079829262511,-0.203476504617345));
#1421=VECTOR('',#1420,1.);
#1422=CARTESIAN_POINT('',(-9.5,5.59267264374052,11.5));
#1423=LINE('',#1422,#1421);
#1424=CARTESIAN_POINT('',(-9.5,5.59267264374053,11.5));
#1425=VERTEX_POINT('',#1424);
#1426=CARTESIAN_POINT('',(-9.5,-3.1214316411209,9.68899804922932));
#1427=VERTEX_POINT('',#1426);
#1428=EDGE_CURVE('E434',#1425,#1427,#1423,.T.);
#1429=ORIENTED_EDGE('',*,*,#1428,.T.);
#1430=DIRECTION('',(1.,0.,0.));
#1431=VECTOR('',#1430,1.);
#1432=CARTESIAN_POINT('',(40.,-3.1214316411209,9.68899804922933));
#1433=LINE('',#1432,#1431);
#1434=EDGE_CURVE('E470',#928,#1427,#1433,.F.);
#1435=ORIENTED_EDGE('',*,*,#1434,.F.);
#1436=ORIENTED_EDGE('',*,*,#929,.T.);
#1437=DIRECTION('',(1.,0.,0.));
#1438=VECTOR('',#1437,1.);
#1439=CARTESIAN_POINT('',(40.,5.59267264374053,11.5));
#1440=LINE('',#1439,#1438);
#1441=EDGE_CURVE('E469',#1425,#920,#1440,.T.);
#1442=ORIENTED_EDGE('',*,*,#1441,.F.);
#1443=EDGE_LOOP('',(#1429,#1435,#1436,#1442));
#1444=FACE_BOUND('',#1443,.T.);
#1445=ADVANCED_FACE('F705',(#1444),#1419,.T.);
#1446=CARTESIAN_POINT('',(40.,-1.75,3.09));
#1447=DIRECTION('',(1.,0.,0.));
#1448=DIRECTION('',(0.,1.,0.));
#1449=AXIS2_PLACEMENT_3D('',#1446,#1447,#1448);
#1450=CYLINDRICAL_SURFACE('',#1449,6.74);
#1451=CARTESIAN_POINT('',(-9.5,-1.75,3.09));
#1452=DIRECTION('',(1.,0.,0.));
#1453=DIRECTION('',(0.,1.,0.));
#1454=AXIS2_PLACEMENT_3D('',#1451,#1452,#1453);
#1455=CIRCLE('',#1454,6.74);
#1456=CARTESIAN_POINT('',(-9.5,-8.4846213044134,3.35921345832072));
#1457=VERTEX_POINT('',#1456);
#1458=EDGE_CURVE('E431',#1427,#1457,#1455,.T.);
#1459=ORIENTED_EDGE('',*,*,#1458,.T.);
#1460=DIRECTION('',(-1.,0.,0.));
#1461=VECTOR('',#1460,1.);
#1462=CARTESIAN_POINT('',(40.,-8.4846213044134,3.35921345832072));
#1463=LINE('',#1462,#1461);
#1464=EDGE_CURVE('E1013',#937,#1457,#1463,.T.);
#1465=ORIENTED_EDGE('',*,*,#1464,.F.);
#1466=ORIENTED_EDGE('',*,*,#938,.T.);
#1467=ORIENTED_EDGE('',*,*,#1434,.T.);
#1468=EDGE_LOOP('',(#1459,#1465,#1466,#1467));
#1469=FACE_BOUND('',#1468,.T.);
#1470=ADVANCED_FACE('F701',(#1469),#1450,.T.);
#1471=CARTESIAN_POINT('',(40.,-8.87,-9.1));
#1472=DIRECTION('',(1.,0.,0.));
#1473=DIRECTION('',(0.,1.,0.));
#1474=AXIS2_PLACEMENT_3D('',#1471,#1472,#1473);
#1475=CYLINDRICAL_SURFACE('',#1474,25.17);
#1476=ORIENTED_EDGE('',*,*,#1441,.T.);
#1477=ORIENTED_EDGE('',*,*,#1165,.T.);
#1478=ORIENTED_EDGE('',*,*,#978,.T.);
#1479=DIRECTION('',(-1.,0.,0.));
#1480=VECTOR('',#1479,1.);
#1481=CARTESIAN_POINT('',(40.,13.,3.35921345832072));
#1482=LINE('',#1481,#1480);
#1483=CARTESIAN_POINT('',(-9.5,13.,3.3592134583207));
#1484=VERTEX_POINT('',#1483);
#1485=EDGE_CURVE('E999',#1484,#970,#1482,.F.);
#1486=ORIENTED_EDGE('',*,*,#1485,.F.);
#1487=CARTESIAN_POINT('',(-9.5,-8.87,-9.1));
#1488=DIRECTION('',(1.,0.,0.));
#1489=DIRECTION('',(0.,1.,0.));
#1490=AXIS2_PLACEMENT_3D('',#1487,#1488,#1489);
#1491=CIRCLE('',#1490,25.17);
#1492=EDGE_CURVE('E435',#1484,#1425,#1491,.T.);
#1493=ORIENTED_EDGE('',*,*,#1492,.T.);
#1494=EDGE_LOOP('',(#1476,#1477,#1478,#1486,#1493));
#1495=FACE_BOUND('',#1494,.T.);
#1496=ADVANCED_FACE('F697',(#1495),#1475,.T.);
#1497=CARTESIAN_POINT('',(6.8,13.,3.35921345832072));
#1498=DIRECTION('',(0.,0.601465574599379,-0.798898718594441));
#1499=DIRECTION('',(0.,-0.798898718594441,-0.601465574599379));
#1500=AXIS2_PLACEMENT_3D('',#1497,#1498,#1499);
#1501=PLANE('',#1500);
#1502=ORIENTED_EDGE('',*,*,#1036,.T.);
#1503=DIRECTION('',(-1.,0.,0.));
#1504=VECTOR('',#1503,1.);
#1505=CARTESIAN_POINT('',(40.,13.,3.35921345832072));
#1506=LINE('',#1505,#1504);
#1507=EDGE_CURVE('E996',#970,#1029,#1506,.F.);
#1508=ORIENTED_EDGE('',*,*,#1507,.F.);
#1509=ORIENTED_EDGE('',*,*,#971,.T.);
#1510=ORIENTED_EDGE('',*,*,#1005,.T.);
#1511=EDGE_LOOP('',(#1502,#1508,#1509,#1510));
#1512=FACE_BOUND('',#1511,.T.);
#1513=ADVANCED_FACE('F693',(#1512),#1501,.T.);
#1514=CARTESIAN_POINT('',(40.,-8.87,-9.1));
#1515=DIRECTION('',(1.,0.,0.));
#1516=DIRECTION('',(0.,1.,0.));
#1517=AXIS2_PLACEMENT_3D('',#1514,#1515,#1516);
#1518=CYLINDRICAL_SURFACE('',#1517,25.17);
#1519=ORIENTED_EDGE('',*,*,#1073,.T.);
#1520=DIRECTION('',(-1.,0.,0.));
#1521=VECTOR('',#1520,1.);
#1522=CARTESIAN_POINT('',(40.,13.,3.35921345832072));
#1523=LINE('',#1522,#1521);
#1524=EDGE_CURVE('E989',#1029,#1065,#1523,.F.);
#1525=ORIENTED_EDGE('',*,*,#1524,.F.);
#1526=ORIENTED_EDGE('',*,*,#1030,.T.);
#1527=ORIENTED_EDGE('',*,*,#1158,.T.);
#1528=EDGE_LOOP('',(#1519,#1525,#1526,#1527));
#1529=FACE_BOUND('',#1528,.T.);
#1530=ADVANCED_FACE('F689',(#1529),#1518,.T.);
#1531=CARTESIAN_POINT('',(15.35,18.5073278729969,7.5055064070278));
#1532=DIRECTION('',(0.,0.601465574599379,-0.798898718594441));
#1533=DIRECTION('',(0.,-0.798898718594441,-0.601465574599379));
#1534=AXIS2_PLACEMENT_3D('',#1531,#1532,#1533);
#1535=PLANE('',#1534);
#1536=ORIENTED_EDGE('',*,*,#1066,.T.);
#1537=ORIENTED_EDGE('',*,*,#1098,.T.);
#1538=ORIENTED_EDGE('',*,*,#1123,.T.);
#1539=DIRECTION('',(-1.,0.,0.));
#1540=VECTOR('',#1539,1.);
#1541=CARTESIAN_POINT('',(40.,13.,3.35921345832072));
#1542=LINE('',#1541,#1540);
#1543=EDGE_CURVE('E986',#1065,#1116,#1542,.F.);
#1544=ORIENTED_EDGE('',*,*,#1543,.F.);
#1545=EDGE_LOOP('',(#1536,#1537,#1538,#1544));
#1546=FACE_BOUND('',#1545,.T.);
#1547=ADVANCED_FACE('F685',(#1546),#1535,.T.);
#1548=CARTESIAN_POINT('',(40.,-8.87,-9.1));
#1549=DIRECTION('',(1.,0.,0.));
#1550=DIRECTION('',(0.,1.,0.));
#1551=AXIS2_PLACEMENT_3D('',#1548,#1549,#1550);
#1552=CYLINDRICAL_SURFACE('',#1551,25.17);
#1553=ORIENTED_EDGE('',*,*,#1117,.T.);
#1554=ORIENTED_EDGE('',*,*,#1151,.T.);
#1555=ORIENTED_EDGE('',*,*,#1205,.T.);
#1556=DIRECTION('',(-1.,0.,0.));
#1557=VECTOR('',#1556,1.);
#1558=CARTESIAN_POINT('',(40.,13.,3.35921345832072));
#1559=LINE('',#1558,#1557);
#1560=EDGE_CURVE('E979',#1116,#1197,#1559,.F.);
#1561=ORIENTED_EDGE('',*,*,#1560,.F.);
#1562=EDGE_LOOP('',(#1553,#1554,#1555,#1561));
#1563=FACE_BOUND('',#1562,.T.);
#1564=ADVANCED_FACE('F681',(#1563),#1552,.T.);
#1565=CARTESIAN_POINT('',(32.05,18.5073278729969,7.5055064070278));
#1566=DIRECTION('',(0.,0.601465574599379,-0.798898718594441));
#1567=DIRECTION('',(0.,-0.798898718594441,-0.601465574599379));
#1568=AXIS2_PLACEMENT_3D('',#1565,#1566,#1567);
#1569=PLANE('',#1568);
#1570=ORIENTED_EDGE('',*,*,#1198,.T.);
#1571=ORIENTED_EDGE('',*,*,#1230,.T.);
#1572=ORIENTED_EDGE('',*,*,#1255,.T.);
#1573=DIRECTION('',(-1.,0.,0.));
#1574=VECTOR('',#1573,1.);
#1575=CARTESIAN_POINT('',(40.,13.,3.35921345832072));
#1576=LINE('',#1575,#1574);
#1577=EDGE_CURVE('E968',#1197,#1248,#1576,.F.);
#1578=ORIENTED_EDGE('',*,*,#1577,.F.);
#1579=EDGE_LOOP('',(#1570,#1571,#1572,#1578));
#1580=FACE_BOUND('',#1579,.T.);
#1581=ADVANCED_FACE('F677',(#1580),#1569,.T.);
#1582=CARTESIAN_POINT('',(40.,-8.87,-9.1));
#1583=DIRECTION('',(1.,0.,0.));
#1584=DIRECTION('',(0.,1.,0.));
#1585=AXIS2_PLACEMENT_3D('',#1582,#1583,#1584);
#1586=CYLINDRICAL_SURFACE('',#1585,25.17);
#1587=CARTESIAN_POINT('',(40.,-8.87,-9.1));
#1588=DIRECTION('',(1.,0.,0.));
#1589=DIRECTION('',(0.,1.,0.));
#1590=AXIS2_PLACEMENT_3D('',#1587,#1588,#1589);
#1591=CIRCLE('',#1590,25.17);
#1592=CARTESIAN_POINT('',(40.,13.,3.3592134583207));
#1593=VERTEX_POINT('',#1592);
#1594=CARTESIAN_POINT('',(40.,5.59267264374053,11.5));
#1595=VERTEX_POINT('',#1594);
#1596=EDGE_CURVE('E427',#1593,#1595,#1591,.T.);
#1597=ORIENTED_EDGE('',*,*,#1596,.F.);
#1598=DIRECTION('',(-1.,0.,0.));
#1599=VECTOR('',#1598,1.);
#1600=CARTESIAN_POINT('',(40.,13.,3.35921345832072));
#1601=LINE('',#1600,#1599);
#1602=EDGE_CURVE('E966',#1248,#1593,#1601,.F.);
#1603=ORIENTED_EDGE('',*,*,#1602,.F.);
#1604=ORIENTED_EDGE('',*,*,#1249,.T.);
#1605=DIRECTION('',(-1.,0.,0.));
#1606=VECTOR('',#1605,1.);
#1607=CARTESIAN_POINT('',(40.,5.59267264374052,11.5));
#1608=LINE('',#1607,#1606);
#1609=EDGE_CURVE('E443',#1595,#600,#1608,.T.);
#1610=ORIENTED_EDGE('',*,*,#1609,.F.);
#1611=EDGE_LOOP('',(#1597,#1603,#1604,#1610));
#1612=FACE_BOUND('',#1611,.T.);
#1613=ADVANCED_FACE('F673',(#1612),#1586,.T.);
#1614=CARTESIAN_POINT('',(40.,5.59267264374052,11.5));
#1615=DIRECTION('',(0.,-0.203476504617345,0.979079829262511));
#1616=DIRECTION('',(0.,0.979079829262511,0.203476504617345));
#1617=AXIS2_PLACEMENT_3D('',#1614,#1615,#1616);
#1618=PLANE('',#1617);
#1619=ORIENTED_EDGE('',*,*,#1609,.T.);
#1620=ORIENTED_EDGE('',*,*,#601,.F.);
#1621=ORIENTED_EDGE('',*,*,#1293,.T.);
#1622=DIRECTION('',(1.,0.,0.));
#1623=VECTOR('',#1622,1.);
#1624=CARTESIAN_POINT('',(40.,-3.1214316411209,9.68899804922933));
#1625=LINE('',#1624,#1623);
#1626=CARTESIAN_POINT('',(40.,-3.1214316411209,9.68899804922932));
#1627=VERTEX_POINT('',#1626);
#1628=EDGE_CURVE('E442',#1627,#1286,#1625,.F.);
#1629=ORIENTED_EDGE('',*,*,#1628,.F.);
#1630=DIRECTION('',(0.,-0.979079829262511,-0.203476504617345));
#1631=VECTOR('',#1630,1.);
#1632=CARTESIAN_POINT('',(40.,5.59267264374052,11.5));
#1633=LINE('',#1632,#1631);
#1634=EDGE_CURVE('E426',#1595,#1627,#1633,.T.);
#1635=ORIENTED_EDGE('',*,*,#1634,.F.);
#1636=EDGE_LOOP('',(#1619,#1620,#1621,#1629,#1635));
#1637=FACE_BOUND('',#1636,.T.);
#1638=ADVANCED_FACE('F669',(#1637),#1618,.T.);
#1639=CARTESIAN_POINT('',(40.,-1.75,3.09));
#1640=DIRECTION('',(1.,0.,0.));
#1641=DIRECTION('',(0.,1.,0.));
#1642=AXIS2_PLACEMENT_3D('',#1639,#1640,#1641);
#1643=CYLINDRICAL_SURFACE('',#1642,6.74);
#1644=CARTESIAN_POINT('',(40.,-1.75,3.09));
#1645=DIRECTION('',(1.,0.,0.));
#1646=DIRECTION('',(0.,1.,0.));
#1647=AXIS2_PLACEMENT_3D('',#1644,#1645,#1646);
#1648=CIRCLE('',#1647,6.74);
#1649=CARTESIAN_POINT('',(40.,-8.4846213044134,3.35921345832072));
#1650=VERTEX_POINT('',#1649);
#1651=EDGE_CURVE('E422',#1627,#1650,#1648,.T.);
#1652=ORIENTED_EDGE('',*,*,#1651,.F.);
#1653=ORIENTED_EDGE('',*,*,#1628,.T.);
#1654=ORIENTED_EDGE('',*,*,#1287,.T.);
#1655=DIRECTION('',(-1.,0.,0.));
#1656=VECTOR('',#1655,1.);
#1657=CARTESIAN_POINT('',(40.,-8.4846213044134,3.35921345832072));
#1658=LINE('',#1657,#1656);
#1659=EDGE_CURVE('E853',#1650,#1277,#1658,.T.);
#1660=ORIENTED_EDGE('',*,*,#1659,.F.);
#1661=EDGE_LOOP('',(#1652,#1653,#1654,#1660));
#1662=FACE_BOUND('',#1661,.T.);
#1663=ADVANCED_FACE('F666',(#1662),#1643,.T.);
#1664=CARTESIAN_POINT('',(40.,-8.4846213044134,3.35921345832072));
#1665=DIRECTION('',(0.,0.,1.));
#1666=DIRECTION('',(0.,1.,0.));
#1667=AXIS2_PLACEMENT_3D('',#1664,#1665,#1666);
#1668=PLANE('',#1667);
#1669=ORIENTED_EDGE('',*,*,#770,.F.);
#1670=ORIENTED_EDGE('',*,*,#1310,.T.);
#1671=ORIENTED_EDGE('',*,*,#712,.T.);
#1672=ORIENTED_EDGE('',*,*,#251,.F.);
#1673=ORIENTED_EDGE('',*,*,#944,.F.);
#1674=ORIENTED_EDGE('',*,*,#1464,.T.);
#1675=DIRECTION('',(0.,1.,0.));
#1676=VECTOR('',#1675,1.);
#1677=CARTESIAN_POINT('',(-9.5,15.5,3.35921345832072));
#1678=LINE('',#1677,#1676);
#1679=CARTESIAN_POINT('',(-9.5,-8.5,3.35921345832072));
#1680=VERTEX_POINT('',#1679);
#1681=EDGE_CURVE('E433',#1457,#1680,#1678,.F.);
#1682=ORIENTED_EDGE('',*,*,#1681,.T.);
#1683=DIRECTION('',(1.,0.,0.));
#1684=VECTOR('',#1683,1.);
#1685=CARTESIAN_POINT('',(40.,-8.5,3.35921345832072));
#1686=LINE('',#1685,#1684);
#1687=CARTESIAN_POINT('',(40.,-8.5,3.35921345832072));
#1688=VERTEX_POINT('',#1687);
#1689=EDGE_CURVE('E421',#1688,#1680,#1686,.F.);
#1690=ORIENTED_EDGE('',*,*,#1689,.F.);
#1691=DIRECTION('',(0.,1.,0.));
#1692=VECTOR('',#1691,1.);
#1693=CARTESIAN_POINT('',(40.,15.5,3.35921345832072));
#1694=LINE('',#1693,#1692);
#1695=EDGE_CURVE('E425',#1650,#1688,#1694,.F.);
#1696=ORIENTED_EDGE('',*,*,#1695,.F.);
#1697=ORIENTED_EDGE('',*,*,#1659,.T.);
#1698=ORIENTED_EDGE('',*,*,#1278,.T.);
#1699=ORIENTED_EDGE('',*,*,#665,.F.);
#1700=EDGE_LOOP('',(#1669,#1670,#1671,#1672,#1673,#1674,#1682,#1690,#1696,#1697,#1698,#1699));
#1701=FACE_BOUND('',#1700,.T.);
#1702=ADVANCED_FACE('F662',(#1701),#1668,.T.);
#1703=CARTESIAN_POINT('',(0.,0.,1.5));
#1704=DIRECTION('',(0.,0.,-1.));
#1705=DIRECTION('',(1.,0.,0.));
#1706=AXIS2_PLACEMENT_3D('',#1703,#1704,#1705);
#1707=CYLINDRICAL_SURFACE('',#1706,2.75);
#1708=ORIENTED_EDGE('',*,*,#1336,.F.);
#1709=DIRECTION('',(0.,0.,-1.));
#1710=VECTOR('',#1709,1.);
#1711=CARTESIAN_POINT('',(0.,-2.75,1.5));
#1712=LINE('',#1711,#1710);
#1713=CARTESIAN_POINT('',(0.,-2.75,0.));
#1714=VERTEX_POINT('',#1713);
#1715=EDGE_CURVE('E948',#1326,#1714,#1712,.T.);
#1716=ORIENTED_EDGE('',*,*,#1715,.T.);
#1717=CARTESIAN_POINT('',(0.,0.,0.));
#1718=DIRECTION('',(0.,0.,-1.));
#1719=DIRECTION('',(1.,0.,0.));
#1720=AXIS2_PLACEMENT_3D('',#1717,#1718,#1719);
#1721=CIRCLE('',#1720,2.75);
#1722=CARTESIAN_POINT('',(0.,2.75,0.));
#1723=VERTEX_POINT('',#1722);
#1724=EDGE_CURVE('E418',#1723,#1714,#1721,.F.);
#1725=ORIENTED_EDGE('',*,*,#1724,.F.);
#1726=DIRECTION('',(0.,0.,-1.));
#1727=VECTOR('',#1726,1.);
#1728=CARTESIAN_POINT('',(0.,2.75,1.5));
#1729=LINE('',#1728,#1727);
#1730=EDGE_CURVE('E927',#1723,#1335,#1729,.F.);
#1731=ORIENTED_EDGE('',*,*,#1730,.T.);
#1732=EDGE_LOOP('',(#1708,#1716,#1725,#1731));
#1733=FACE_BOUND('',#1732,.T.);
#1734=ADVANCED_FACE('F658',(#1733),#1707,.F.);
#1735=CARTESIAN_POINT('',(0.,0.,1.5));
#1736=DIRECTION('',(0.,0.,-1.));
#1737=DIRECTION('',(1.,0.,0.));
#1738=AXIS2_PLACEMENT_3D('',#1735,#1736,#1737);
#1739=CYLINDRICAL_SURFACE('',#1738,2.75);
#1740=CARTESIAN_POINT('',(0.,0.,0.));
#1741=DIRECTION('',(0.,0.,-1.));
#1742=DIRECTION('',(1.,0.,0.));
#1743=AXIS2_PLACEMENT_3D('',#1740,#1741,#1742);
#1744=CIRCLE('',#1743,2.75);
#1745=EDGE_CURVE('E415',#1714,#1723,#1744,.F.);
#1746=ORIENTED_EDGE('',*,*,#1745,.F.);
#1747=ORIENTED_EDGE('',*,*,#1715,.F.);
#1748=ORIENTED_EDGE('',*,*,#1357,.F.);
#1749=ORIENTED_EDGE('',*,*,#1730,.F.);
#1750=EDGE_LOOP('',(#1746,#1747,#1748,#1749));
#1751=FACE_BOUND('',#1750,.T.);
#1752=ADVANCED_FACE('F654',(#1751),#1739,.F.);
#1753=CARTESIAN_POINT('',(30.5,0.,1.5));
#1754=DIRECTION('',(0.,0.,-1.));
#1755=DIRECTION('',(1.,0.,0.));
#1756=AXIS2_PLACEMENT_3D('',#1753,#1754,#1755);
#1757=CYLINDRICAL_SURFACE('',#1756,2.75);
#1758=ORIENTED_EDGE('',*,*,#1386,.F.);
#1759=DIRECTION('',(0.,0.,-1.));
#1760=VECTOR('',#1759,1.);
#1761=CARTESIAN_POINT('',(30.5,-2.75,1.5));
#1762=LINE('',#1761,#1760);
#1763=CARTESIAN_POINT('',(30.5,-2.75,0.));
#1764=VERTEX_POINT('',#1763);
#1765=EDGE_CURVE('E932',#1376,#1764,#1762,.T.);
#1766=ORIENTED_EDGE('',*,*,#1765,.T.);
#1767=CARTESIAN_POINT('',(30.5,0.,0.));
#1768=DIRECTION('',(0.,0.,-1.));
#1769=DIRECTION('',(1.,0.,0.));
#1770=AXIS2_PLACEMENT_3D('',#1767,#1768,#1769);
#1771=CIRCLE('',#1770,2.75);
#1772=CARTESIAN_POINT('',(30.5,2.75,0.));
#1773=VERTEX_POINT('',#1772);
#1774=EDGE_CURVE('E412',#1773,#1764,#1771,.F.);
#1775=ORIENTED_EDGE('',*,*,#1774,.F.);
#1776=DIRECTION('',(0.,0.,-1.));
#1777=VECTOR('',#1776,1.);
#1778=CARTESIAN_POINT('',(30.5,2.75,1.5));
#1779=LINE('',#1778,#1777);
#1780=EDGE_CURVE('E438',#1773,#1385,#1779,.F.);
#1781=ORIENTED_EDGE('',*,*,#1780,.T.);
#1782=EDGE_LOOP('',(#1758,#1766,#1775,#1781));
#1783=FACE_BOUND('',#1782,.T.);
#1784=ADVANCED_FACE('F650',(#1783),#1757,.F.);
#1785=CARTESIAN_POINT('',(30.5,0.,1.5));
#1786=DIRECTION('',(0.,0.,-1.));
#1787=DIRECTION('',(1.,0.,0.));
#1788=AXIS2_PLACEMENT_3D('',#1785,#1786,#1787);
#1789=CYLINDRICAL_SURFACE('',#1788,2.75);
#1790=CARTESIAN_POINT('',(30.5,0.,0.));
#1791=DIRECTION('',(0.,0.,-1.));
#1792=DIRECTION('',(1.,0.,0.));
#1793=AXIS2_PLACEMENT_3D('',#1790,#1791,#1792);
#1794=CIRCLE('',#1793,2.75);
#1795=EDGE_CURVE('E408',#1764,#1773,#1794,.F.);
#1796=ORIENTED_EDGE('',*,*,#1795,.F.);
#1797=ORIENTED_EDGE('',*,*,#1765,.F.);
#1798=ORIENTED_EDGE('',*,*,#1407,.F.);
#1799=ORIENTED_EDGE('',*,*,#1780,.F.);
#1800=EDGE_LOOP('',(#1796,#1797,#1798,#1799));
#1801=FACE_BOUND('',#1800,.T.);
#1802=ADVANCED_FACE('F646',(#1801),#1789,.F.);
#1803=CARTESIAN_POINT('',(-9.5,15.5,0.));
#1804=DIRECTION('',(1.,0.,0.));
#1805=DIRECTION('',(0.,1.,0.));
#1806=AXIS2_PLACEMENT_3D('',#1803,#1804,#1805);
#1807=PLANE('',#1806);
#1808=DIRECTION('',(0.,-1.,0.));
#1809=VECTOR('',#1808,1.);
#1810=CARTESIAN_POINT('',(-9.5,-8.5,0.));
#1811=LINE('',#1810,#1809);
#1812=CARTESIAN_POINT('',(-9.5,-8.5,0.));
#1813=VERTEX_POINT('',#1812);
#1814=CARTESIAN_POINT('',(-9.5,13.,0.));
#1815=VERTEX_POINT('',#1814);
#1816=EDGE_CURVE('E411',#1813,#1815,#1811,.F.);
#1817=ORIENTED_EDGE('',*,*,#1816,.F.);
#1818=DIRECTION('',(0.,0.,1.));
#1819=VECTOR('',#1818,1.);
#1820=CARTESIAN_POINT('',(-9.5,-8.5,3.35921345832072));
#1821=LINE('',#1820,#1819);
#1822=EDGE_CURVE('E1016',#1680,#1813,#1821,.F.);
#1823=ORIENTED_EDGE('',*,*,#1822,.F.);
#1824=ORIENTED_EDGE('',*,*,#1681,.F.);
#1825=ORIENTED_EDGE('',*,*,#1458,.F.);
#1826=ORIENTED_EDGE('',*,*,#1428,.F.);
#1827=ORIENTED_EDGE('',*,*,#1492,.F.);
#1828=DIRECTION('',(0.,0.,1.));
#1829=VECTOR('',#1828,1.);
#1830=CARTESIAN_POINT('',(-9.5,13.,0.));
#1831=LINE('',#1830,#1829);
#1832=EDGE_CURVE('E1004',#1815,#1484,#1831,.T.);
#1833=ORIENTED_EDGE('',*,*,#1832,.F.);
#1834=EDGE_LOOP('',(#1817,#1823,#1824,#1825,#1826,#1827,#1833));
#1835=FACE_BOUND('',#1834,.T.);
#1836=ADVANCED_FACE('F642',(#1835),#1807,.F.);
#1837=CARTESIAN_POINT('',(40.,13.,0.));
#1838=DIRECTION('',(0.,1.,0.));
#1839=DIRECTION('',(-1.,0.,0.));
#1840=AXIS2_PLACEMENT_3D('',#1837,#1838,#1839);
#1841=PLANE('',#1840);
#1842=DIRECTION('',(0.,0.,1.));
#1843=VECTOR('',#1842,1.);
#1844=CARTESIAN_POINT('',(40.,13.,0.));
#1845=LINE('',#1844,#1843);
#1846=CARTESIAN_POINT('',(40.,13.,0.));
#1847=VERTEX_POINT('',#1846);
#1848=EDGE_CURVE('E430',#1847,#1593,#1845,.T.);
#1849=ORIENTED_EDGE('',*,*,#1848,.F.);
#1850=DIRECTION('',(1.,0.,0.));
#1851=VECTOR('',#1850,1.);
#1852=CARTESIAN_POINT('',(40.,13.,0.));
#1853=LINE('',#1852,#1851);
#1854=EDGE_CURVE('E970',#1815,#1847,#1853,.T.);
#1855=ORIENTED_EDGE('',*,*,#1854,.F.);
#1856=ORIENTED_EDGE('',*,*,#1832,.T.);
#1857=ORIENTED_EDGE('',*,*,#1485,.T.);
#1858=ORIENTED_EDGE('',*,*,#1507,.T.);
#1859=ORIENTED_EDGE('',*,*,#1524,.T.);
#1860=ORIENTED_EDGE('',*,*,#1543,.T.);
#1861=ORIENTED_EDGE('',*,*,#1560,.T.);
#1862=ORIENTED_EDGE('',*,*,#1577,.T.);
#1863=ORIENTED_EDGE('',*,*,#1602,.T.);
#1864=EDGE_LOOP('',(#1849,#1855,#1856,#1857,#1858,#1859,#1860,#1861,#1862,#1863));
#1865=FACE_BOUND('',#1864,.T.);
#1866=ADVANCED_FACE('F639',(#1865),#1841,.T.);
#1867=CARTESIAN_POINT('',(40.,15.5,0.));
#1868=DIRECTION('',(1.,0.,0.));
#1869=DIRECTION('',(0.,1.,0.));
#1870=AXIS2_PLACEMENT_3D('',#1867,#1868,#1869);
#1871=PLANE('',#1870);
#1872=ORIENTED_EDGE('',*,*,#1695,.T.);
#1873=DIRECTION('',(0.,0.,1.));
#1874=VECTOR('',#1873,1.);
#1875=CARTESIAN_POINT('',(40.,-8.5,3.35921345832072));
#1876=LINE('',#1875,#1874);
#1877=CARTESIAN_POINT('',(40.,-8.5,0.));
#1878=VERTEX_POINT('',#1877);
#1879=EDGE_CURVE('E32',#1878,#1688,#1876,.T.);
#1880=ORIENTED_EDGE('',*,*,#1879,.F.);
#1881=DIRECTION('',(0.,-1.,0.));
#1882=VECTOR('',#1881,1.);
#1883=CARTESIAN_POINT('',(40.,-8.5,0.));
#1884=LINE('',#1883,#1882);
#1885=EDGE_CURVE('E23',#1847,#1878,#1884,.T.);
#1886=ORIENTED_EDGE('',*,*,#1885,.F.);
#1887=ORIENTED_EDGE('',*,*,#1848,.T.);
#1888=ORIENTED_EDGE('',*,*,#1596,.T.);
#1889=ORIENTED_EDGE('',*,*,#1634,.T.);
#1890=ORIENTED_EDGE('',*,*,#1651,.T.);
#1891=EDGE_LOOP('',(#1872,#1880,#1886,#1887,#1888,#1889,#1890));
#1892=FACE_BOUND('',#1891,.T.);
#1893=ADVANCED_FACE('F631',(#1892),#1871,.T.);
#1894=CARTESIAN_POINT('',(40.,-8.5,3.35921345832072));
#1895=DIRECTION('',(0.,-1.,0.));
#1896=DIRECTION('',(1.,0.,0.));
#1897=AXIS2_PLACEMENT_3D('',#1894,#1895,#1896);
#1898=PLANE('',#1897);
#1899=ORIENTED_EDGE('',*,*,#1879,.T.);
#1900=ORIENTED_EDGE('',*,*,#1689,.T.);
#1901=ORIENTED_EDGE('',*,*,#1822,.T.);
#1902=DIRECTION('',(1.,0.,0.));
#1903=VECTOR('',#1902,1.);
#1904=CARTESIAN_POINT('',(40.,-8.5,0.));
#1905=LINE('',#1904,#1903);
#1906=EDGE_CURVE('E9',#1878,#1813,#1905,.F.);
#1907=ORIENTED_EDGE('',*,*,#1906,.F.);
#1908=EDGE_LOOP('',(#1899,#1900,#1901,#1907));
#1909=FACE_BOUND('',#1908,.T.);
#1910=ADVANCED_FACE('F624',(#1909),#1898,.T.);
#1911=CARTESIAN_POINT('',(40.,-8.5,0.));
#1912=DIRECTION('',(0.,0.,-1.));
#1913=DIRECTION('',(1.,0.,0.));
#1914=AXIS2_PLACEMENT_3D('',#1911,#1912,#1913);
#1915=PLANE('',#1914);
#1916=ORIENTED_EDGE('',*,*,#1885,.T.);
#1917=ORIENTED_EDGE('',*,*,#1906,.T.);
#1918=ORIENTED_EDGE('',*,*,#1816,.T.);
#1919=ORIENTED_EDGE('',*,*,#1854,.T.);
#1920=EDGE_LOOP('',(#1916,#1917,#1918,#1919));
#1921=FACE_BOUND('',#1920,.T.);
#1922=ORIENTED_EDGE('',*,*,#1774,.T.);
#1923=ORIENTED_EDGE('',*,*,#1795,.T.);
#1924=EDGE_LOOP('',(#1922,#1923));
#1925=FACE_BOUND('',#1924,.T.);
#1926=ORIENTED_EDGE('',*,*,#1724,.T.);
#1927=ORIENTED_EDGE('',*,*,#1745,.T.);
#1928=EDGE_LOOP('',(#1926,#1927));
#1929=FACE_BOUND('',#1928,.T.);
#1930=ADVANCED_FACE('F622',(#1921,#1925,#1929),#1915,.T.);
#1931=CLOSED_SHELL('',(#52,#123,#157,#228,#270,#301,#343,#367,#409,#433,#473,#513,#555,#579,
#627,#669,#700,#741,#782,#804,#837,#856,#889,#908,#949,#986,#1011,#1040,#1077,#1102,#1131,#1172,
#1209,#1234,#1263,#1297,#1314,#1346,#1364,#1396,#1414,#1445,#1470,#1496,#1513,#1530,#1547,#1564,
#1581,#1613,#1638,#1663,#1702,#1734,#1752,#1784,#1802,#1836,#1866,#1893,#1910,#1930));
#1932=MANIFOLD_SOLID_BREP('B1',#1931);
#1933=ADVANCED_BREP_SHAPE_REPRESENTATION('',(#18,#1932),#14);
#1934=SHAPE_DEFINITION_REPRESENTATION(#9,#1933);
ENDSEC;
END-ISO-10303-21;
